# Generated by FakeRAM 2.0
VERSION 5.7 ;
BUSBITCHARS "[]" ;
PROPERTYDEFINITIONS
  MACRO width INTEGER ;
  MACRO depth INTEGER ;
  MACRO banks INTEGER ;
END PROPERTYDEFINITIONS
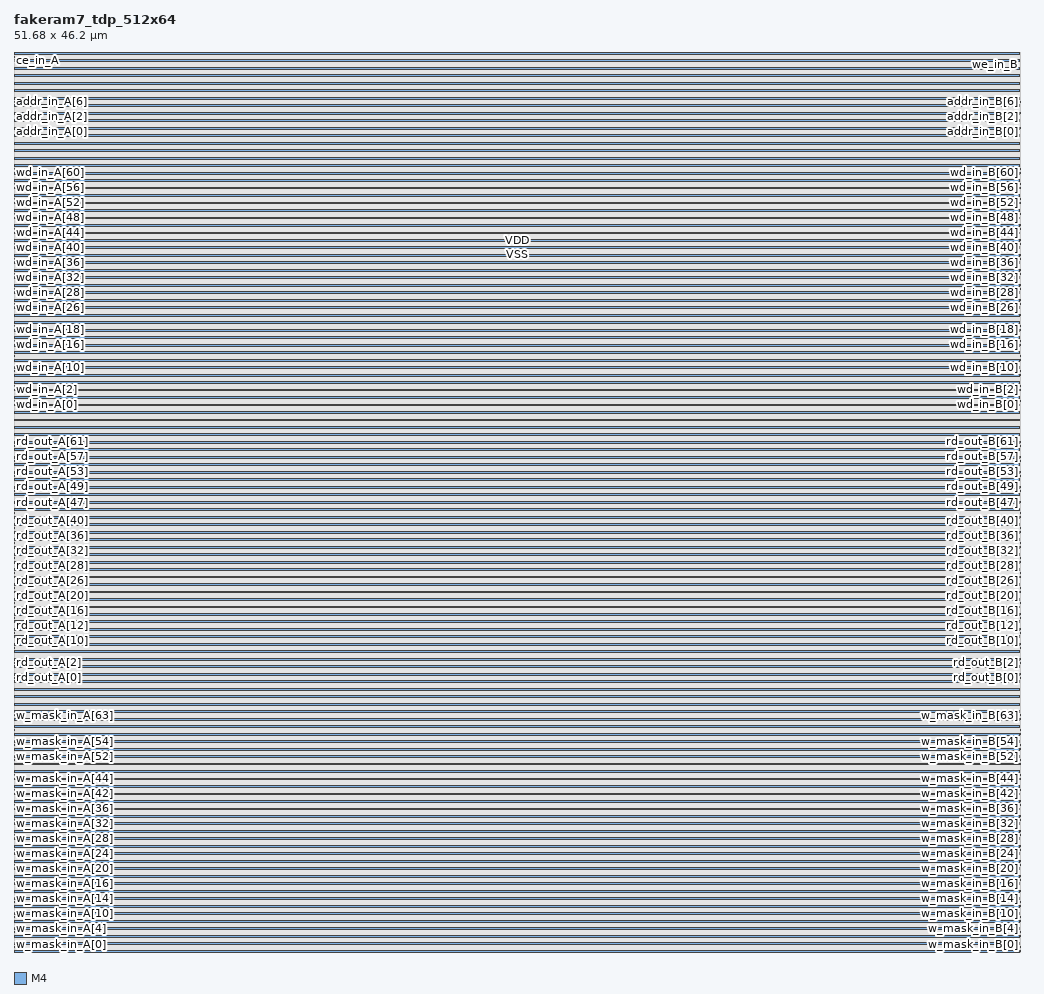
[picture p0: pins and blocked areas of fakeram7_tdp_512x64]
MACRO fakeram7_tdp_512x64
  PROPERTY width 64 ;
  PROPERTY depth 512 ;
  PROPERTY banks 4 ;
  FOREIGN fakeram7_tdp_512x64 0 0 ;
  SYMMETRY X Y ;
  SIZE 51.680 BY 46.200 ;
  CLASS BLOCK ;
  PIN w_mask_in_A[0]
    DIRECTION INPUT ;
    USE SIGNAL ;
    SHAPE ABUTMENT ;
    PORT
      LAYER M4 ;
      RECT 0.000 0.048 0.024 0.072 ;
    END
  END w_mask_in_A[0]
  PIN w_mask_in_B[0]
    DIRECTION INPUT ;
    USE SIGNAL ;
    SHAPE ABUTMENT ;
    PORT
      LAYER M4 ;
      RECT 51.656 0.048 51.680 0.072 ;
    END
  END w_mask_in_B[0]
  PIN w_mask_in_A[1]
    DIRECTION INPUT ;
    USE SIGNAL ;
    SHAPE ABUTMENT ;
    PORT
      LAYER M4 ;
      RECT 0.000 0.240 0.024 0.264 ;
    END
  END w_mask_in_A[1]
  PIN w_mask_in_B[1]
    DIRECTION INPUT ;
    USE SIGNAL ;
    SHAPE ABUTMENT ;
    PORT
      LAYER M4 ;
      RECT 51.656 0.240 51.680 0.264 ;
    END
  END w_mask_in_B[1]
  PIN w_mask_in_A[2]
    DIRECTION INPUT ;
    USE SIGNAL ;
    SHAPE ABUTMENT ;
    PORT
      LAYER M4 ;
      RECT 0.000 0.432 0.024 0.456 ;
    END
  END w_mask_in_A[2]
  PIN w_mask_in_B[2]
    DIRECTION INPUT ;
    USE SIGNAL ;
    SHAPE ABUTMENT ;
    PORT
      LAYER M4 ;
      RECT 51.656 0.432 51.680 0.456 ;
    END
  END w_mask_in_B[2]
  PIN w_mask_in_A[3]
    DIRECTION INPUT ;
    USE SIGNAL ;
    SHAPE ABUTMENT ;
    PORT
      LAYER M4 ;
      RECT 0.000 0.624 0.024 0.648 ;
    END
  END w_mask_in_A[3]
  PIN w_mask_in_B[3]
    DIRECTION INPUT ;
    USE SIGNAL ;
    SHAPE ABUTMENT ;
    PORT
      LAYER M4 ;
      RECT 51.656 0.624 51.680 0.648 ;
    END
  END w_mask_in_B[3]
  PIN w_mask_in_A[4]
    DIRECTION INPUT ;
    USE SIGNAL ;
    SHAPE ABUTMENT ;
    PORT
      LAYER M4 ;
      RECT 0.000 0.816 0.024 0.840 ;
    END
  END w_mask_in_A[4]
  PIN w_mask_in_B[4]
    DIRECTION INPUT ;
    USE SIGNAL ;
    SHAPE ABUTMENT ;
    PORT
      LAYER M4 ;
      RECT 51.656 0.816 51.680 0.840 ;
    END
  END w_mask_in_B[4]
  PIN w_mask_in_A[5]
    DIRECTION INPUT ;
    USE SIGNAL ;
    SHAPE ABUTMENT ;
    PORT
      LAYER M4 ;
      RECT 0.000 1.008 0.024 1.032 ;
    END
  END w_mask_in_A[5]
  PIN w_mask_in_B[5]
    DIRECTION INPUT ;
    USE SIGNAL ;
    SHAPE ABUTMENT ;
    PORT
      LAYER M4 ;
      RECT 51.656 1.008 51.680 1.032 ;
    END
  END w_mask_in_B[5]
  PIN w_mask_in_A[6]
    DIRECTION INPUT ;
    USE SIGNAL ;
    SHAPE ABUTMENT ;
    PORT
      LAYER M4 ;
      RECT 0.000 1.200 0.024 1.224 ;
    END
  END w_mask_in_A[6]
  PIN w_mask_in_B[6]
    DIRECTION INPUT ;
    USE SIGNAL ;
    SHAPE ABUTMENT ;
    PORT
      LAYER M4 ;
      RECT 51.656 1.200 51.680 1.224 ;
    END
  END w_mask_in_B[6]
  PIN w_mask_in_A[7]
    DIRECTION INPUT ;
    USE SIGNAL ;
    SHAPE ABUTMENT ;
    PORT
      LAYER M4 ;
      RECT 0.000 1.392 0.024 1.416 ;
    END
  END w_mask_in_A[7]
  PIN w_mask_in_B[7]
    DIRECTION INPUT ;
    USE SIGNAL ;
    SHAPE ABUTMENT ;
    PORT
      LAYER M4 ;
      RECT 51.656 1.392 51.680 1.416 ;
    END
  END w_mask_in_B[7]
  PIN w_mask_in_A[8]
    DIRECTION INPUT ;
    USE SIGNAL ;
    SHAPE ABUTMENT ;
    PORT
      LAYER M4 ;
      RECT 0.000 1.584 0.024 1.608 ;
    END
  END w_mask_in_A[8]
  PIN w_mask_in_B[8]
    DIRECTION INPUT ;
    USE SIGNAL ;
    SHAPE ABUTMENT ;
    PORT
      LAYER M4 ;
      RECT 51.656 1.584 51.680 1.608 ;
    END
  END w_mask_in_B[8]
  PIN w_mask_in_A[9]
    DIRECTION INPUT ;
    USE SIGNAL ;
    SHAPE ABUTMENT ;
    PORT
      LAYER M4 ;
      RECT 0.000 1.776 0.024 1.800 ;
    END
  END w_mask_in_A[9]
  PIN w_mask_in_B[9]
    DIRECTION INPUT ;
    USE SIGNAL ;
    SHAPE ABUTMENT ;
    PORT
      LAYER M4 ;
      RECT 51.656 1.776 51.680 1.800 ;
    END
  END w_mask_in_B[9]
  PIN w_mask_in_A[10]
    DIRECTION INPUT ;
    USE SIGNAL ;
    SHAPE ABUTMENT ;
    PORT
      LAYER M4 ;
      RECT 0.000 1.968 0.024 1.992 ;
    END
  END w_mask_in_A[10]
  PIN w_mask_in_B[10]
    DIRECTION INPUT ;
    USE SIGNAL ;
    SHAPE ABUTMENT ;
    PORT
      LAYER M4 ;
      RECT 51.656 1.968 51.680 1.992 ;
    END
  END w_mask_in_B[10]
  PIN w_mask_in_A[11]
    DIRECTION INPUT ;
    USE SIGNAL ;
    SHAPE ABUTMENT ;
    PORT
      LAYER M4 ;
      RECT 0.000 2.160 0.024 2.184 ;
    END
  END w_mask_in_A[11]
  PIN w_mask_in_B[11]
    DIRECTION INPUT ;
    USE SIGNAL ;
    SHAPE ABUTMENT ;
    PORT
      LAYER M4 ;
      RECT 51.656 2.160 51.680 2.184 ;
    END
  END w_mask_in_B[11]
  PIN w_mask_in_A[12]
    DIRECTION INPUT ;
    USE SIGNAL ;
    SHAPE ABUTMENT ;
    PORT
      LAYER M4 ;
      RECT 0.000 2.352 0.024 2.376 ;
    END
  END w_mask_in_A[12]
  PIN w_mask_in_B[12]
    DIRECTION INPUT ;
    USE SIGNAL ;
    SHAPE ABUTMENT ;
    PORT
      LAYER M4 ;
      RECT 51.656 2.352 51.680 2.376 ;
    END
  END w_mask_in_B[12]
  PIN w_mask_in_A[13]
    DIRECTION INPUT ;
    USE SIGNAL ;
    SHAPE ABUTMENT ;
    PORT
      LAYER M4 ;
      RECT 0.000 2.544 0.024 2.568 ;
    END
  END w_mask_in_A[13]
  PIN w_mask_in_B[13]
    DIRECTION INPUT ;
    USE SIGNAL ;
    SHAPE ABUTMENT ;
    PORT
      LAYER M4 ;
      RECT 51.656 2.544 51.680 2.568 ;
    END
  END w_mask_in_B[13]
  PIN w_mask_in_A[14]
    DIRECTION INPUT ;
    USE SIGNAL ;
    SHAPE ABUTMENT ;
    PORT
      LAYER M4 ;
      RECT 0.000 2.736 0.024 2.760 ;
    END
  END w_mask_in_A[14]
  PIN w_mask_in_B[14]
    DIRECTION INPUT ;
    USE SIGNAL ;
    SHAPE ABUTMENT ;
    PORT
      LAYER M4 ;
      RECT 51.656 2.736 51.680 2.760 ;
    END
  END w_mask_in_B[14]
  PIN w_mask_in_A[15]
    DIRECTION INPUT ;
    USE SIGNAL ;
    SHAPE ABUTMENT ;
    PORT
      LAYER M4 ;
      RECT 0.000 2.928 0.024 2.952 ;
    END
  END w_mask_in_A[15]
  PIN w_mask_in_B[15]
    DIRECTION INPUT ;
    USE SIGNAL ;
    SHAPE ABUTMENT ;
    PORT
      LAYER M4 ;
      RECT 51.656 2.928 51.680 2.952 ;
    END
  END w_mask_in_B[15]
  PIN w_mask_in_A[16]
    DIRECTION INPUT ;
    USE SIGNAL ;
    SHAPE ABUTMENT ;
    PORT
      LAYER M4 ;
      RECT 0.000 3.120 0.024 3.144 ;
    END
  END w_mask_in_A[16]
  PIN w_mask_in_B[16]
    DIRECTION INPUT ;
    USE SIGNAL ;
    SHAPE ABUTMENT ;
    PORT
      LAYER M4 ;
      RECT 51.656 3.120 51.680 3.144 ;
    END
  END w_mask_in_B[16]
  PIN w_mask_in_A[17]
    DIRECTION INPUT ;
    USE SIGNAL ;
    SHAPE ABUTMENT ;
    PORT
      LAYER M4 ;
      RECT 0.000 3.312 0.024 3.336 ;
    END
  END w_mask_in_A[17]
  PIN w_mask_in_B[17]
    DIRECTION INPUT ;
    USE SIGNAL ;
    SHAPE ABUTMENT ;
    PORT
      LAYER M4 ;
      RECT 51.656 3.312 51.680 3.336 ;
    END
  END w_mask_in_B[17]
  PIN w_mask_in_A[18]
    DIRECTION INPUT ;
    USE SIGNAL ;
    SHAPE ABUTMENT ;
    PORT
      LAYER M4 ;
      RECT 0.000 3.504 0.024 3.528 ;
    END
  END w_mask_in_A[18]
  PIN w_mask_in_B[18]
    DIRECTION INPUT ;
    USE SIGNAL ;
    SHAPE ABUTMENT ;
    PORT
      LAYER M4 ;
      RECT 51.656 3.504 51.680 3.528 ;
    END
  END w_mask_in_B[18]
  PIN w_mask_in_A[19]
    DIRECTION INPUT ;
    USE SIGNAL ;
    SHAPE ABUTMENT ;
    PORT
      LAYER M4 ;
      RECT 0.000 3.696 0.024 3.720 ;
    END
  END w_mask_in_A[19]
  PIN w_mask_in_B[19]
    DIRECTION INPUT ;
    USE SIGNAL ;
    SHAPE ABUTMENT ;
    PORT
      LAYER M4 ;
      RECT 51.656 3.696 51.680 3.720 ;
    END
  END w_mask_in_B[19]
  PIN w_mask_in_A[20]
    DIRECTION INPUT ;
    USE SIGNAL ;
    SHAPE ABUTMENT ;
    PORT
      LAYER M4 ;
      RECT 0.000 3.888 0.024 3.912 ;
    END
  END w_mask_in_A[20]
  PIN w_mask_in_B[20]
    DIRECTION INPUT ;
    USE SIGNAL ;
    SHAPE ABUTMENT ;
    PORT
      LAYER M4 ;
      RECT 51.656 3.888 51.680 3.912 ;
    END
  END w_mask_in_B[20]
  PIN w_mask_in_A[21]
    DIRECTION INPUT ;
    USE SIGNAL ;
    SHAPE ABUTMENT ;
    PORT
      LAYER M4 ;
      RECT 0.000 4.080 0.024 4.104 ;
    END
  END w_mask_in_A[21]
  PIN w_mask_in_B[21]
    DIRECTION INPUT ;
    USE SIGNAL ;
    SHAPE ABUTMENT ;
    PORT
      LAYER M4 ;
      RECT 51.656 4.080 51.680 4.104 ;
    END
  END w_mask_in_B[21]
  PIN w_mask_in_A[22]
    DIRECTION INPUT ;
    USE SIGNAL ;
    SHAPE ABUTMENT ;
    PORT
      LAYER M4 ;
      RECT 0.000 4.272 0.024 4.296 ;
    END
  END w_mask_in_A[22]
  PIN w_mask_in_B[22]
    DIRECTION INPUT ;
    USE SIGNAL ;
    SHAPE ABUTMENT ;
    PORT
      LAYER M4 ;
      RECT 51.656 4.272 51.680 4.296 ;
    END
  END w_mask_in_B[22]
  PIN w_mask_in_A[23]
    DIRECTION INPUT ;
    USE SIGNAL ;
    SHAPE ABUTMENT ;
    PORT
      LAYER M4 ;
      RECT 0.000 4.464 0.024 4.488 ;
    END
  END w_mask_in_A[23]
  PIN w_mask_in_B[23]
    DIRECTION INPUT ;
    USE SIGNAL ;
    SHAPE ABUTMENT ;
    PORT
      LAYER M4 ;
      RECT 51.656 4.464 51.680 4.488 ;
    END
  END w_mask_in_B[23]
  PIN w_mask_in_A[24]
    DIRECTION INPUT ;
    USE SIGNAL ;
    SHAPE ABUTMENT ;
    PORT
      LAYER M4 ;
      RECT 0.000 4.656 0.024 4.680 ;
    END
  END w_mask_in_A[24]
  PIN w_mask_in_B[24]
    DIRECTION INPUT ;
    USE SIGNAL ;
    SHAPE ABUTMENT ;
    PORT
      LAYER M4 ;
      RECT 51.656 4.656 51.680 4.680 ;
    END
  END w_mask_in_B[24]
  PIN w_mask_in_A[25]
    DIRECTION INPUT ;
    USE SIGNAL ;
    SHAPE ABUTMENT ;
    PORT
      LAYER M4 ;
      RECT 0.000 4.848 0.024 4.872 ;
    END
  END w_mask_in_A[25]
  PIN w_mask_in_B[25]
    DIRECTION INPUT ;
    USE SIGNAL ;
    SHAPE ABUTMENT ;
    PORT
      LAYER M4 ;
      RECT 51.656 4.848 51.680 4.872 ;
    END
  END w_mask_in_B[25]
  PIN w_mask_in_A[26]
    DIRECTION INPUT ;
    USE SIGNAL ;
    SHAPE ABUTMENT ;
    PORT
      LAYER M4 ;
      RECT 0.000 5.040 0.024 5.064 ;
    END
  END w_mask_in_A[26]
  PIN w_mask_in_B[26]
    DIRECTION INPUT ;
    USE SIGNAL ;
    SHAPE ABUTMENT ;
    PORT
      LAYER M4 ;
      RECT 51.656 5.040 51.680 5.064 ;
    END
  END w_mask_in_B[26]
  PIN w_mask_in_A[27]
    DIRECTION INPUT ;
    USE SIGNAL ;
    SHAPE ABUTMENT ;
    PORT
      LAYER M4 ;
      RECT 0.000 5.232 0.024 5.256 ;
    END
  END w_mask_in_A[27]
  PIN w_mask_in_B[27]
    DIRECTION INPUT ;
    USE SIGNAL ;
    SHAPE ABUTMENT ;
    PORT
      LAYER M4 ;
      RECT 51.656 5.232 51.680 5.256 ;
    END
  END w_mask_in_B[27]
  PIN w_mask_in_A[28]
    DIRECTION INPUT ;
    USE SIGNAL ;
    SHAPE ABUTMENT ;
    PORT
      LAYER M4 ;
      RECT 0.000 5.424 0.024 5.448 ;
    END
  END w_mask_in_A[28]
  PIN w_mask_in_B[28]
    DIRECTION INPUT ;
    USE SIGNAL ;
    SHAPE ABUTMENT ;
    PORT
      LAYER M4 ;
      RECT 51.656 5.424 51.680 5.448 ;
    END
  END w_mask_in_B[28]
  PIN w_mask_in_A[29]
    DIRECTION INPUT ;
    USE SIGNAL ;
    SHAPE ABUTMENT ;
    PORT
      LAYER M4 ;
      RECT 0.000 5.616 0.024 5.640 ;
    END
  END w_mask_in_A[29]
  PIN w_mask_in_B[29]
    DIRECTION INPUT ;
    USE SIGNAL ;
    SHAPE ABUTMENT ;
    PORT
      LAYER M4 ;
      RECT 51.656 5.616 51.680 5.640 ;
    END
  END w_mask_in_B[29]
  PIN w_mask_in_A[30]
    DIRECTION INPUT ;
    USE SIGNAL ;
    SHAPE ABUTMENT ;
    PORT
      LAYER M4 ;
      RECT 0.000 5.808 0.024 5.832 ;
    END
  END w_mask_in_A[30]
  PIN w_mask_in_B[30]
    DIRECTION INPUT ;
    USE SIGNAL ;
    SHAPE ABUTMENT ;
    PORT
      LAYER M4 ;
      RECT 51.656 5.808 51.680 5.832 ;
    END
  END w_mask_in_B[30]
  PIN w_mask_in_A[31]
    DIRECTION INPUT ;
    USE SIGNAL ;
    SHAPE ABUTMENT ;
    PORT
      LAYER M4 ;
      RECT 0.000 6.000 0.024 6.024 ;
    END
  END w_mask_in_A[31]
  PIN w_mask_in_B[31]
    DIRECTION INPUT ;
    USE SIGNAL ;
    SHAPE ABUTMENT ;
    PORT
      LAYER M4 ;
      RECT 51.656 6.000 51.680 6.024 ;
    END
  END w_mask_in_B[31]
  PIN w_mask_in_A[32]
    DIRECTION INPUT ;
    USE SIGNAL ;
    SHAPE ABUTMENT ;
    PORT
      LAYER M4 ;
      RECT 0.000 6.192 0.024 6.216 ;
    END
  END w_mask_in_A[32]
  PIN w_mask_in_B[32]
    DIRECTION INPUT ;
    USE SIGNAL ;
    SHAPE ABUTMENT ;
    PORT
      LAYER M4 ;
      RECT 51.656 6.192 51.680 6.216 ;
    END
  END w_mask_in_B[32]
  PIN w_mask_in_A[33]
    DIRECTION INPUT ;
    USE SIGNAL ;
    SHAPE ABUTMENT ;
    PORT
      LAYER M4 ;
      RECT 0.000 6.384 0.024 6.408 ;
    END
  END w_mask_in_A[33]
  PIN w_mask_in_B[33]
    DIRECTION INPUT ;
    USE SIGNAL ;
    SHAPE ABUTMENT ;
    PORT
      LAYER M4 ;
      RECT 51.656 6.384 51.680 6.408 ;
    END
  END w_mask_in_B[33]
  PIN w_mask_in_A[34]
    DIRECTION INPUT ;
    USE SIGNAL ;
    SHAPE ABUTMENT ;
    PORT
      LAYER M4 ;
      RECT 0.000 6.576 0.024 6.600 ;
    END
  END w_mask_in_A[34]
  PIN w_mask_in_B[34]
    DIRECTION INPUT ;
    USE SIGNAL ;
    SHAPE ABUTMENT ;
    PORT
      LAYER M4 ;
      RECT 51.656 6.576 51.680 6.600 ;
    END
  END w_mask_in_B[34]
  PIN w_mask_in_A[35]
    DIRECTION INPUT ;
    USE SIGNAL ;
    SHAPE ABUTMENT ;
    PORT
      LAYER M4 ;
      RECT 0.000 6.768 0.024 6.792 ;
    END
  END w_mask_in_A[35]
  PIN w_mask_in_B[35]
    DIRECTION INPUT ;
    USE SIGNAL ;
    SHAPE ABUTMENT ;
    PORT
      LAYER M4 ;
      RECT 51.656 6.768 51.680 6.792 ;
    END
  END w_mask_in_B[35]
  PIN w_mask_in_A[36]
    DIRECTION INPUT ;
    USE SIGNAL ;
    SHAPE ABUTMENT ;
    PORT
      LAYER M4 ;
      RECT 0.000 6.960 0.024 6.984 ;
    END
  END w_mask_in_A[36]
  PIN w_mask_in_B[36]
    DIRECTION INPUT ;
    USE SIGNAL ;
    SHAPE ABUTMENT ;
    PORT
      LAYER M4 ;
      RECT 51.656 6.960 51.680 6.984 ;
    END
  END w_mask_in_B[36]
  PIN w_mask_in_A[37]
    DIRECTION INPUT ;
    USE SIGNAL ;
    SHAPE ABUTMENT ;
    PORT
      LAYER M4 ;
      RECT 0.000 7.152 0.024 7.176 ;
    END
  END w_mask_in_A[37]
  PIN w_mask_in_B[37]
    DIRECTION INPUT ;
    USE SIGNAL ;
    SHAPE ABUTMENT ;
    PORT
      LAYER M4 ;
      RECT 51.656 7.152 51.680 7.176 ;
    END
  END w_mask_in_B[37]
  PIN w_mask_in_A[38]
    DIRECTION INPUT ;
    USE SIGNAL ;
    SHAPE ABUTMENT ;
    PORT
      LAYER M4 ;
      RECT 0.000 7.344 0.024 7.368 ;
    END
  END w_mask_in_A[38]
  PIN w_mask_in_B[38]
    DIRECTION INPUT ;
    USE SIGNAL ;
    SHAPE ABUTMENT ;
    PORT
      LAYER M4 ;
      RECT 51.656 7.344 51.680 7.368 ;
    END
  END w_mask_in_B[38]
  PIN w_mask_in_A[39]
    DIRECTION INPUT ;
    USE SIGNAL ;
    SHAPE ABUTMENT ;
    PORT
      LAYER M4 ;
      RECT 0.000 7.536 0.024 7.560 ;
    END
  END w_mask_in_A[39]
  PIN w_mask_in_B[39]
    DIRECTION INPUT ;
    USE SIGNAL ;
    SHAPE ABUTMENT ;
    PORT
      LAYER M4 ;
      RECT 51.656 7.536 51.680 7.560 ;
    END
  END w_mask_in_B[39]
  PIN w_mask_in_A[40]
    DIRECTION INPUT ;
    USE SIGNAL ;
    SHAPE ABUTMENT ;
    PORT
      LAYER M4 ;
      RECT 0.000 7.728 0.024 7.752 ;
    END
  END w_mask_in_A[40]
  PIN w_mask_in_B[40]
    DIRECTION INPUT ;
    USE SIGNAL ;
    SHAPE ABUTMENT ;
    PORT
      LAYER M4 ;
      RECT 51.656 7.728 51.680 7.752 ;
    END
  END w_mask_in_B[40]
  PIN w_mask_in_A[41]
    DIRECTION INPUT ;
    USE SIGNAL ;
    SHAPE ABUTMENT ;
    PORT
      LAYER M4 ;
      RECT 0.000 7.920 0.024 7.944 ;
    END
  END w_mask_in_A[41]
  PIN w_mask_in_B[41]
    DIRECTION INPUT ;
    USE SIGNAL ;
    SHAPE ABUTMENT ;
    PORT
      LAYER M4 ;
      RECT 51.656 7.920 51.680 7.944 ;
    END
  END w_mask_in_B[41]
  PIN w_mask_in_A[42]
    DIRECTION INPUT ;
    USE SIGNAL ;
    SHAPE ABUTMENT ;
    PORT
      LAYER M4 ;
      RECT 0.000 8.112 0.024 8.136 ;
    END
  END w_mask_in_A[42]
  PIN w_mask_in_B[42]
    DIRECTION INPUT ;
    USE SIGNAL ;
    SHAPE ABUTMENT ;
    PORT
      LAYER M4 ;
      RECT 51.656 8.112 51.680 8.136 ;
    END
  END w_mask_in_B[42]
  PIN w_mask_in_A[43]
    DIRECTION INPUT ;
    USE SIGNAL ;
    SHAPE ABUTMENT ;
    PORT
      LAYER M4 ;
      RECT 0.000 8.304 0.024 8.328 ;
    END
  END w_mask_in_A[43]
  PIN w_mask_in_B[43]
    DIRECTION INPUT ;
    USE SIGNAL ;
    SHAPE ABUTMENT ;
    PORT
      LAYER M4 ;
      RECT 51.656 8.304 51.680 8.328 ;
    END
  END w_mask_in_B[43]
  PIN w_mask_in_A[44]
    DIRECTION INPUT ;
    USE SIGNAL ;
    SHAPE ABUTMENT ;
    PORT
      LAYER M4 ;
      RECT 0.000 8.496 0.024 8.520 ;
    END
  END w_mask_in_A[44]
  PIN w_mask_in_B[44]
    DIRECTION INPUT ;
    USE SIGNAL ;
    SHAPE ABUTMENT ;
    PORT
      LAYER M4 ;
      RECT 51.656 8.496 51.680 8.520 ;
    END
  END w_mask_in_B[44]
  PIN w_mask_in_A[45]
    DIRECTION INPUT ;
    USE SIGNAL ;
    SHAPE ABUTMENT ;
    PORT
      LAYER M4 ;
      RECT 0.000 8.688 0.024 8.712 ;
    END
  END w_mask_in_A[45]
  PIN w_mask_in_B[45]
    DIRECTION INPUT ;
    USE SIGNAL ;
    SHAPE ABUTMENT ;
    PORT
      LAYER M4 ;
      RECT 51.656 8.688 51.680 8.712 ;
    END
  END w_mask_in_B[45]
  PIN w_mask_in_A[46]
    DIRECTION INPUT ;
    USE SIGNAL ;
    SHAPE ABUTMENT ;
    PORT
      LAYER M4 ;
      RECT 0.000 8.880 0.024 8.904 ;
    END
  END w_mask_in_A[46]
  PIN w_mask_in_B[46]
    DIRECTION INPUT ;
    USE SIGNAL ;
    SHAPE ABUTMENT ;
    PORT
      LAYER M4 ;
      RECT 51.656 8.880 51.680 8.904 ;
    END
  END w_mask_in_B[46]
  PIN w_mask_in_A[47]
    DIRECTION INPUT ;
    USE SIGNAL ;
    SHAPE ABUTMENT ;
    PORT
      LAYER M4 ;
      RECT 0.000 9.072 0.024 9.096 ;
    END
  END w_mask_in_A[47]
  PIN w_mask_in_B[47]
    DIRECTION INPUT ;
    USE SIGNAL ;
    SHAPE ABUTMENT ;
    PORT
      LAYER M4 ;
      RECT 51.656 9.072 51.680 9.096 ;
    END
  END w_mask_in_B[47]
  PIN w_mask_in_A[48]
    DIRECTION INPUT ;
    USE SIGNAL ;
    SHAPE ABUTMENT ;
    PORT
      LAYER M4 ;
      RECT 0.000 9.264 0.024 9.288 ;
    END
  END w_mask_in_A[48]
  PIN w_mask_in_B[48]
    DIRECTION INPUT ;
    USE SIGNAL ;
    SHAPE ABUTMENT ;
    PORT
      LAYER M4 ;
      RECT 51.656 9.264 51.680 9.288 ;
    END
  END w_mask_in_B[48]
  PIN w_mask_in_A[49]
    DIRECTION INPUT ;
    USE SIGNAL ;
    SHAPE ABUTMENT ;
    PORT
      LAYER M4 ;
      RECT 0.000 9.456 0.024 9.480 ;
    END
  END w_mask_in_A[49]
  PIN w_mask_in_B[49]
    DIRECTION INPUT ;
    USE SIGNAL ;
    SHAPE ABUTMENT ;
    PORT
      LAYER M4 ;
      RECT 51.656 9.456 51.680 9.480 ;
    END
  END w_mask_in_B[49]
  PIN w_mask_in_A[50]
    DIRECTION INPUT ;
    USE SIGNAL ;
    SHAPE ABUTMENT ;
    PORT
      LAYER M4 ;
      RECT 0.000 9.648 0.024 9.672 ;
    END
  END w_mask_in_A[50]
  PIN w_mask_in_B[50]
    DIRECTION INPUT ;
    USE SIGNAL ;
    SHAPE ABUTMENT ;
    PORT
      LAYER M4 ;
      RECT 51.656 9.648 51.680 9.672 ;
    END
  END w_mask_in_B[50]
  PIN w_mask_in_A[51]
    DIRECTION INPUT ;
    USE SIGNAL ;
    SHAPE ABUTMENT ;
    PORT
      LAYER M4 ;
      RECT 0.000 9.840 0.024 9.864 ;
    END
  END w_mask_in_A[51]
  PIN w_mask_in_B[51]
    DIRECTION INPUT ;
    USE SIGNAL ;
    SHAPE ABUTMENT ;
    PORT
      LAYER M4 ;
      RECT 51.656 9.840 51.680 9.864 ;
    END
  END w_mask_in_B[51]
  PIN w_mask_in_A[52]
    DIRECTION INPUT ;
    USE SIGNAL ;
    SHAPE ABUTMENT ;
    PORT
      LAYER M4 ;
      RECT 0.000 10.032 0.024 10.056 ;
    END
  END w_mask_in_A[52]
  PIN w_mask_in_B[52]
    DIRECTION INPUT ;
    USE SIGNAL ;
    SHAPE ABUTMENT ;
    PORT
      LAYER M4 ;
      RECT 51.656 10.032 51.680 10.056 ;
    END
  END w_mask_in_B[52]
  PIN w_mask_in_A[53]
    DIRECTION INPUT ;
    USE SIGNAL ;
    SHAPE ABUTMENT ;
    PORT
      LAYER M4 ;
      RECT 0.000 10.224 0.024 10.248 ;
    END
  END w_mask_in_A[53]
  PIN w_mask_in_B[53]
    DIRECTION INPUT ;
    USE SIGNAL ;
    SHAPE ABUTMENT ;
    PORT
      LAYER M4 ;
      RECT 51.656 10.224 51.680 10.248 ;
    END
  END w_mask_in_B[53]
  PIN w_mask_in_A[54]
    DIRECTION INPUT ;
    USE SIGNAL ;
    SHAPE ABUTMENT ;
    PORT
      LAYER M4 ;
      RECT 0.000 10.416 0.024 10.440 ;
    END
  END w_mask_in_A[54]
  PIN w_mask_in_B[54]
    DIRECTION INPUT ;
    USE SIGNAL ;
    SHAPE ABUTMENT ;
    PORT
      LAYER M4 ;
      RECT 51.656 10.416 51.680 10.440 ;
    END
  END w_mask_in_B[54]
  PIN w_mask_in_A[55]
    DIRECTION INPUT ;
    USE SIGNAL ;
    SHAPE ABUTMENT ;
    PORT
      LAYER M4 ;
      RECT 0.000 10.608 0.024 10.632 ;
    END
  END w_mask_in_A[55]
  PIN w_mask_in_B[55]
    DIRECTION INPUT ;
    USE SIGNAL ;
    SHAPE ABUTMENT ;
    PORT
      LAYER M4 ;
      RECT 51.656 10.608 51.680 10.632 ;
    END
  END w_mask_in_B[55]
  PIN w_mask_in_A[56]
    DIRECTION INPUT ;
    USE SIGNAL ;
    SHAPE ABUTMENT ;
    PORT
      LAYER M4 ;
      RECT 0.000 10.800 0.024 10.824 ;
    END
  END w_mask_in_A[56]
  PIN w_mask_in_B[56]
    DIRECTION INPUT ;
    USE SIGNAL ;
    SHAPE ABUTMENT ;
    PORT
      LAYER M4 ;
      RECT 51.656 10.800 51.680 10.824 ;
    END
  END w_mask_in_B[56]
  PIN w_mask_in_A[57]
    DIRECTION INPUT ;
    USE SIGNAL ;
    SHAPE ABUTMENT ;
    PORT
      LAYER M4 ;
      RECT 0.000 10.992 0.024 11.016 ;
    END
  END w_mask_in_A[57]
  PIN w_mask_in_B[57]
    DIRECTION INPUT ;
    USE SIGNAL ;
    SHAPE ABUTMENT ;
    PORT
      LAYER M4 ;
      RECT 51.656 10.992 51.680 11.016 ;
    END
  END w_mask_in_B[57]
  PIN w_mask_in_A[58]
    DIRECTION INPUT ;
    USE SIGNAL ;
    SHAPE ABUTMENT ;
    PORT
      LAYER M4 ;
      RECT 0.000 11.184 0.024 11.208 ;
    END
  END w_mask_in_A[58]
  PIN w_mask_in_B[58]
    DIRECTION INPUT ;
    USE SIGNAL ;
    SHAPE ABUTMENT ;
    PORT
      LAYER M4 ;
      RECT 51.656 11.184 51.680 11.208 ;
    END
  END w_mask_in_B[58]
  PIN w_mask_in_A[59]
    DIRECTION INPUT ;
    USE SIGNAL ;
    SHAPE ABUTMENT ;
    PORT
      LAYER M4 ;
      RECT 0.000 11.376 0.024 11.400 ;
    END
  END w_mask_in_A[59]
  PIN w_mask_in_B[59]
    DIRECTION INPUT ;
    USE SIGNAL ;
    SHAPE ABUTMENT ;
    PORT
      LAYER M4 ;
      RECT 51.656 11.376 51.680 11.400 ;
    END
  END w_mask_in_B[59]
  PIN w_mask_in_A[60]
    DIRECTION INPUT ;
    USE SIGNAL ;
    SHAPE ABUTMENT ;
    PORT
      LAYER M4 ;
      RECT 0.000 11.568 0.024 11.592 ;
    END
  END w_mask_in_A[60]
  PIN w_mask_in_B[60]
    DIRECTION INPUT ;
    USE SIGNAL ;
    SHAPE ABUTMENT ;
    PORT
      LAYER M4 ;
      RECT 51.656 11.568 51.680 11.592 ;
    END
  END w_mask_in_B[60]
  PIN w_mask_in_A[61]
    DIRECTION INPUT ;
    USE SIGNAL ;
    SHAPE ABUTMENT ;
    PORT
      LAYER M4 ;
      RECT 0.000 11.760 0.024 11.784 ;
    END
  END w_mask_in_A[61]
  PIN w_mask_in_B[61]
    DIRECTION INPUT ;
    USE SIGNAL ;
    SHAPE ABUTMENT ;
    PORT
      LAYER M4 ;
      RECT 51.656 11.760 51.680 11.784 ;
    END
  END w_mask_in_B[61]
  PIN w_mask_in_A[62]
    DIRECTION INPUT ;
    USE SIGNAL ;
    SHAPE ABUTMENT ;
    PORT
      LAYER M4 ;
      RECT 0.000 11.952 0.024 11.976 ;
    END
  END w_mask_in_A[62]
  PIN w_mask_in_B[62]
    DIRECTION INPUT ;
    USE SIGNAL ;
    SHAPE ABUTMENT ;
    PORT
      LAYER M4 ;
      RECT 51.656 11.952 51.680 11.976 ;
    END
  END w_mask_in_B[62]
  PIN w_mask_in_A[63]
    DIRECTION INPUT ;
    USE SIGNAL ;
    SHAPE ABUTMENT ;
    PORT
      LAYER M4 ;
      RECT 0.000 12.144 0.024 12.168 ;
    END
  END w_mask_in_A[63]
  PIN w_mask_in_B[63]
    DIRECTION INPUT ;
    USE SIGNAL ;
    SHAPE ABUTMENT ;
    PORT
      LAYER M4 ;
      RECT 51.656 12.144 51.680 12.168 ;
    END
  END w_mask_in_B[63]
  PIN rd_out_A[0]
    DIRECTION OUTPUT ;
    USE SIGNAL ;
    SHAPE ABUTMENT ;
    PORT
      LAYER M4 ;
      RECT 0.000 14.064 0.024 14.088 ;
    END
  END rd_out_A[0]
  PIN rd_out_B[0]
    DIRECTION OUTPUT ;
    USE SIGNAL ;
    SHAPE ABUTMENT ;
    PORT
      LAYER M4 ;
      RECT 51.656 14.064 51.680 14.088 ;
    END
  END rd_out_B[0]
  PIN rd_out_A[1]
    DIRECTION OUTPUT ;
    USE SIGNAL ;
    SHAPE ABUTMENT ;
    PORT
      LAYER M4 ;
      RECT 0.000 14.256 0.024 14.280 ;
    END
  END rd_out_A[1]
  PIN rd_out_B[1]
    DIRECTION OUTPUT ;
    USE SIGNAL ;
    SHAPE ABUTMENT ;
    PORT
      LAYER M4 ;
      RECT 51.656 14.256 51.680 14.280 ;
    END
  END rd_out_B[1]
  PIN rd_out_A[2]
    DIRECTION OUTPUT ;
    USE SIGNAL ;
    SHAPE ABUTMENT ;
    PORT
      LAYER M4 ;
      RECT 0.000 14.448 0.024 14.472 ;
    END
  END rd_out_A[2]
  PIN rd_out_B[2]
    DIRECTION OUTPUT ;
    USE SIGNAL ;
    SHAPE ABUTMENT ;
    PORT
      LAYER M4 ;
      RECT 51.656 14.448 51.680 14.472 ;
    END
  END rd_out_B[2]
  PIN rd_out_A[3]
    DIRECTION OUTPUT ;
    USE SIGNAL ;
    SHAPE ABUTMENT ;
    PORT
      LAYER M4 ;
      RECT 0.000 14.640 0.024 14.664 ;
    END
  END rd_out_A[3]
  PIN rd_out_B[3]
    DIRECTION OUTPUT ;
    USE SIGNAL ;
    SHAPE ABUTMENT ;
    PORT
      LAYER M4 ;
      RECT 51.656 14.640 51.680 14.664 ;
    END
  END rd_out_B[3]
  PIN rd_out_A[4]
    DIRECTION OUTPUT ;
    USE SIGNAL ;
    SHAPE ABUTMENT ;
    PORT
      LAYER M4 ;
      RECT 0.000 14.832 0.024 14.856 ;
    END
  END rd_out_A[4]
  PIN rd_out_B[4]
    DIRECTION OUTPUT ;
    USE SIGNAL ;
    SHAPE ABUTMENT ;
    PORT
      LAYER M4 ;
      RECT 51.656 14.832 51.680 14.856 ;
    END
  END rd_out_B[4]
  PIN rd_out_A[5]
    DIRECTION OUTPUT ;
    USE SIGNAL ;
    SHAPE ABUTMENT ;
    PORT
      LAYER M4 ;
      RECT 0.000 15.024 0.024 15.048 ;
    END
  END rd_out_A[5]
  PIN rd_out_B[5]
    DIRECTION OUTPUT ;
    USE SIGNAL ;
    SHAPE ABUTMENT ;
    PORT
      LAYER M4 ;
      RECT 51.656 15.024 51.680 15.048 ;
    END
  END rd_out_B[5]
  PIN rd_out_A[6]
    DIRECTION OUTPUT ;
    USE SIGNAL ;
    SHAPE ABUTMENT ;
    PORT
      LAYER M4 ;
      RECT 0.000 15.216 0.024 15.240 ;
    END
  END rd_out_A[6]
  PIN rd_out_B[6]
    DIRECTION OUTPUT ;
    USE SIGNAL ;
    SHAPE ABUTMENT ;
    PORT
      LAYER M4 ;
      RECT 51.656 15.216 51.680 15.240 ;
    END
  END rd_out_B[6]
  PIN rd_out_A[7]
    DIRECTION OUTPUT ;
    USE SIGNAL ;
    SHAPE ABUTMENT ;
    PORT
      LAYER M4 ;
      RECT 0.000 15.408 0.024 15.432 ;
    END
  END rd_out_A[7]
  PIN rd_out_B[7]
    DIRECTION OUTPUT ;
    USE SIGNAL ;
    SHAPE ABUTMENT ;
    PORT
      LAYER M4 ;
      RECT 51.656 15.408 51.680 15.432 ;
    END
  END rd_out_B[7]
  PIN rd_out_A[8]
    DIRECTION OUTPUT ;
    USE SIGNAL ;
    SHAPE ABUTMENT ;
    PORT
      LAYER M4 ;
      RECT 0.000 15.600 0.024 15.624 ;
    END
  END rd_out_A[8]
  PIN rd_out_B[8]
    DIRECTION OUTPUT ;
    USE SIGNAL ;
    SHAPE ABUTMENT ;
    PORT
      LAYER M4 ;
      RECT 51.656 15.600 51.680 15.624 ;
    END
  END rd_out_B[8]
  PIN rd_out_A[9]
    DIRECTION OUTPUT ;
    USE SIGNAL ;
    SHAPE ABUTMENT ;
    PORT
      LAYER M4 ;
      RECT 0.000 15.792 0.024 15.816 ;
    END
  END rd_out_A[9]
  PIN rd_out_B[9]
    DIRECTION OUTPUT ;
    USE SIGNAL ;
    SHAPE ABUTMENT ;
    PORT
      LAYER M4 ;
      RECT 51.656 15.792 51.680 15.816 ;
    END
  END rd_out_B[9]
  PIN rd_out_A[10]
    DIRECTION OUTPUT ;
    USE SIGNAL ;
    SHAPE ABUTMENT ;
    PORT
      LAYER M4 ;
      RECT 0.000 15.984 0.024 16.008 ;
    END
  END rd_out_A[10]
  PIN rd_out_B[10]
    DIRECTION OUTPUT ;
    USE SIGNAL ;
    SHAPE ABUTMENT ;
    PORT
      LAYER M4 ;
      RECT 51.656 15.984 51.680 16.008 ;
    END
  END rd_out_B[10]
  PIN rd_out_A[11]
    DIRECTION OUTPUT ;
    USE SIGNAL ;
    SHAPE ABUTMENT ;
    PORT
      LAYER M4 ;
      RECT 0.000 16.176 0.024 16.200 ;
    END
  END rd_out_A[11]
  PIN rd_out_B[11]
    DIRECTION OUTPUT ;
    USE SIGNAL ;
    SHAPE ABUTMENT ;
    PORT
      LAYER M4 ;
      RECT 51.656 16.176 51.680 16.200 ;
    END
  END rd_out_B[11]
  PIN rd_out_A[12]
    DIRECTION OUTPUT ;
    USE SIGNAL ;
    SHAPE ABUTMENT ;
    PORT
      LAYER M4 ;
      RECT 0.000 16.368 0.024 16.392 ;
    END
  END rd_out_A[12]
  PIN rd_out_B[12]
    DIRECTION OUTPUT ;
    USE SIGNAL ;
    SHAPE ABUTMENT ;
    PORT
      LAYER M4 ;
      RECT 51.656 16.368 51.680 16.392 ;
    END
  END rd_out_B[12]
  PIN rd_out_A[13]
    DIRECTION OUTPUT ;
    USE SIGNAL ;
    SHAPE ABUTMENT ;
    PORT
      LAYER M4 ;
      RECT 0.000 16.560 0.024 16.584 ;
    END
  END rd_out_A[13]
  PIN rd_out_B[13]
    DIRECTION OUTPUT ;
    USE SIGNAL ;
    SHAPE ABUTMENT ;
    PORT
      LAYER M4 ;
      RECT 51.656 16.560 51.680 16.584 ;
    END
  END rd_out_B[13]
  PIN rd_out_A[14]
    DIRECTION OUTPUT ;
    USE SIGNAL ;
    SHAPE ABUTMENT ;
    PORT
      LAYER M4 ;
      RECT 0.000 16.752 0.024 16.776 ;
    END
  END rd_out_A[14]
  PIN rd_out_B[14]
    DIRECTION OUTPUT ;
    USE SIGNAL ;
    SHAPE ABUTMENT ;
    PORT
      LAYER M4 ;
      RECT 51.656 16.752 51.680 16.776 ;
    END
  END rd_out_B[14]
  PIN rd_out_A[15]
    DIRECTION OUTPUT ;
    USE SIGNAL ;
    SHAPE ABUTMENT ;
    PORT
      LAYER M4 ;
      RECT 0.000 16.944 0.024 16.968 ;
    END
  END rd_out_A[15]
  PIN rd_out_B[15]
    DIRECTION OUTPUT ;
    USE SIGNAL ;
    SHAPE ABUTMENT ;
    PORT
      LAYER M4 ;
      RECT 51.656 16.944 51.680 16.968 ;
    END
  END rd_out_B[15]
  PIN rd_out_A[16]
    DIRECTION OUTPUT ;
    USE SIGNAL ;
    SHAPE ABUTMENT ;
    PORT
      LAYER M4 ;
      RECT 0.000 17.136 0.024 17.160 ;
    END
  END rd_out_A[16]
  PIN rd_out_B[16]
    DIRECTION OUTPUT ;
    USE SIGNAL ;
    SHAPE ABUTMENT ;
    PORT
      LAYER M4 ;
      RECT 51.656 17.136 51.680 17.160 ;
    END
  END rd_out_B[16]
  PIN rd_out_A[17]
    DIRECTION OUTPUT ;
    USE SIGNAL ;
    SHAPE ABUTMENT ;
    PORT
      LAYER M4 ;
      RECT 0.000 17.328 0.024 17.352 ;
    END
  END rd_out_A[17]
  PIN rd_out_B[17]
    DIRECTION OUTPUT ;
    USE SIGNAL ;
    SHAPE ABUTMENT ;
    PORT
      LAYER M4 ;
      RECT 51.656 17.328 51.680 17.352 ;
    END
  END rd_out_B[17]
  PIN rd_out_A[18]
    DIRECTION OUTPUT ;
    USE SIGNAL ;
    SHAPE ABUTMENT ;
    PORT
      LAYER M4 ;
      RECT 0.000 17.520 0.024 17.544 ;
    END
  END rd_out_A[18]
  PIN rd_out_B[18]
    DIRECTION OUTPUT ;
    USE SIGNAL ;
    SHAPE ABUTMENT ;
    PORT
      LAYER M4 ;
      RECT 51.656 17.520 51.680 17.544 ;
    END
  END rd_out_B[18]
  PIN rd_out_A[19]
    DIRECTION OUTPUT ;
    USE SIGNAL ;
    SHAPE ABUTMENT ;
    PORT
      LAYER M4 ;
      RECT 0.000 17.712 0.024 17.736 ;
    END
  END rd_out_A[19]
  PIN rd_out_B[19]
    DIRECTION OUTPUT ;
    USE SIGNAL ;
    SHAPE ABUTMENT ;
    PORT
      LAYER M4 ;
      RECT 51.656 17.712 51.680 17.736 ;
    END
  END rd_out_B[19]
  PIN rd_out_A[20]
    DIRECTION OUTPUT ;
    USE SIGNAL ;
    SHAPE ABUTMENT ;
    PORT
      LAYER M4 ;
      RECT 0.000 17.904 0.024 17.928 ;
    END
  END rd_out_A[20]
  PIN rd_out_B[20]
    DIRECTION OUTPUT ;
    USE SIGNAL ;
    SHAPE ABUTMENT ;
    PORT
      LAYER M4 ;
      RECT 51.656 17.904 51.680 17.928 ;
    END
  END rd_out_B[20]
  PIN rd_out_A[21]
    DIRECTION OUTPUT ;
    USE SIGNAL ;
    SHAPE ABUTMENT ;
    PORT
      LAYER M4 ;
      RECT 0.000 18.096 0.024 18.120 ;
    END
  END rd_out_A[21]
  PIN rd_out_B[21]
    DIRECTION OUTPUT ;
    USE SIGNAL ;
    SHAPE ABUTMENT ;
    PORT
      LAYER M4 ;
      RECT 51.656 18.096 51.680 18.120 ;
    END
  END rd_out_B[21]
  PIN rd_out_A[22]
    DIRECTION OUTPUT ;
    USE SIGNAL ;
    SHAPE ABUTMENT ;
    PORT
      LAYER M4 ;
      RECT 0.000 18.288 0.024 18.312 ;
    END
  END rd_out_A[22]
  PIN rd_out_B[22]
    DIRECTION OUTPUT ;
    USE SIGNAL ;
    SHAPE ABUTMENT ;
    PORT
      LAYER M4 ;
      RECT 51.656 18.288 51.680 18.312 ;
    END
  END rd_out_B[22]
  PIN rd_out_A[23]
    DIRECTION OUTPUT ;
    USE SIGNAL ;
    SHAPE ABUTMENT ;
    PORT
      LAYER M4 ;
      RECT 0.000 18.480 0.024 18.504 ;
    END
  END rd_out_A[23]
  PIN rd_out_B[23]
    DIRECTION OUTPUT ;
    USE SIGNAL ;
    SHAPE ABUTMENT ;
    PORT
      LAYER M4 ;
      RECT 51.656 18.480 51.680 18.504 ;
    END
  END rd_out_B[23]
  PIN rd_out_A[24]
    DIRECTION OUTPUT ;
    USE SIGNAL ;
    SHAPE ABUTMENT ;
    PORT
      LAYER M4 ;
      RECT 0.000 18.672 0.024 18.696 ;
    END
  END rd_out_A[24]
  PIN rd_out_B[24]
    DIRECTION OUTPUT ;
    USE SIGNAL ;
    SHAPE ABUTMENT ;
    PORT
      LAYER M4 ;
      RECT 51.656 18.672 51.680 18.696 ;
    END
  END rd_out_B[24]
  PIN rd_out_A[25]
    DIRECTION OUTPUT ;
    USE SIGNAL ;
    SHAPE ABUTMENT ;
    PORT
      LAYER M4 ;
      RECT 0.000 18.864 0.024 18.888 ;
    END
  END rd_out_A[25]
  PIN rd_out_B[25]
    DIRECTION OUTPUT ;
    USE SIGNAL ;
    SHAPE ABUTMENT ;
    PORT
      LAYER M4 ;
      RECT 51.656 18.864 51.680 18.888 ;
    END
  END rd_out_B[25]
  PIN rd_out_A[26]
    DIRECTION OUTPUT ;
    USE SIGNAL ;
    SHAPE ABUTMENT ;
    PORT
      LAYER M4 ;
      RECT 0.000 19.056 0.024 19.080 ;
    END
  END rd_out_A[26]
  PIN rd_out_B[26]
    DIRECTION OUTPUT ;
    USE SIGNAL ;
    SHAPE ABUTMENT ;
    PORT
      LAYER M4 ;
      RECT 51.656 19.056 51.680 19.080 ;
    END
  END rd_out_B[26]
  PIN rd_out_A[27]
    DIRECTION OUTPUT ;
    USE SIGNAL ;
    SHAPE ABUTMENT ;
    PORT
      LAYER M4 ;
      RECT 0.000 19.248 0.024 19.272 ;
    END
  END rd_out_A[27]
  PIN rd_out_B[27]
    DIRECTION OUTPUT ;
    USE SIGNAL ;
    SHAPE ABUTMENT ;
    PORT
      LAYER M4 ;
      RECT 51.656 19.248 51.680 19.272 ;
    END
  END rd_out_B[27]
  PIN rd_out_A[28]
    DIRECTION OUTPUT ;
    USE SIGNAL ;
    SHAPE ABUTMENT ;
    PORT
      LAYER M4 ;
      RECT 0.000 19.440 0.024 19.464 ;
    END
  END rd_out_A[28]
  PIN rd_out_B[28]
    DIRECTION OUTPUT ;
    USE SIGNAL ;
    SHAPE ABUTMENT ;
    PORT
      LAYER M4 ;
      RECT 51.656 19.440 51.680 19.464 ;
    END
  END rd_out_B[28]
  PIN rd_out_A[29]
    DIRECTION OUTPUT ;
    USE SIGNAL ;
    SHAPE ABUTMENT ;
    PORT
      LAYER M4 ;
      RECT 0.000 19.632 0.024 19.656 ;
    END
  END rd_out_A[29]
  PIN rd_out_B[29]
    DIRECTION OUTPUT ;
    USE SIGNAL ;
    SHAPE ABUTMENT ;
    PORT
      LAYER M4 ;
      RECT 51.656 19.632 51.680 19.656 ;
    END
  END rd_out_B[29]
  PIN rd_out_A[30]
    DIRECTION OUTPUT ;
    USE SIGNAL ;
    SHAPE ABUTMENT ;
    PORT
      LAYER M4 ;
      RECT 0.000 19.824 0.024 19.848 ;
    END
  END rd_out_A[30]
  PIN rd_out_B[30]
    DIRECTION OUTPUT ;
    USE SIGNAL ;
    SHAPE ABUTMENT ;
    PORT
      LAYER M4 ;
      RECT 51.656 19.824 51.680 19.848 ;
    END
  END rd_out_B[30]
  PIN rd_out_A[31]
    DIRECTION OUTPUT ;
    USE SIGNAL ;
    SHAPE ABUTMENT ;
    PORT
      LAYER M4 ;
      RECT 0.000 20.016 0.024 20.040 ;
    END
  END rd_out_A[31]
  PIN rd_out_B[31]
    DIRECTION OUTPUT ;
    USE SIGNAL ;
    SHAPE ABUTMENT ;
    PORT
      LAYER M4 ;
      RECT 51.656 20.016 51.680 20.040 ;
    END
  END rd_out_B[31]
  PIN rd_out_A[32]
    DIRECTION OUTPUT ;
    USE SIGNAL ;
    SHAPE ABUTMENT ;
    PORT
      LAYER M4 ;
      RECT 0.000 20.208 0.024 20.232 ;
    END
  END rd_out_A[32]
  PIN rd_out_B[32]
    DIRECTION OUTPUT ;
    USE SIGNAL ;
    SHAPE ABUTMENT ;
    PORT
      LAYER M4 ;
      RECT 51.656 20.208 51.680 20.232 ;
    END
  END rd_out_B[32]
  PIN rd_out_A[33]
    DIRECTION OUTPUT ;
    USE SIGNAL ;
    SHAPE ABUTMENT ;
    PORT
      LAYER M4 ;
      RECT 0.000 20.400 0.024 20.424 ;
    END
  END rd_out_A[33]
  PIN rd_out_B[33]
    DIRECTION OUTPUT ;
    USE SIGNAL ;
    SHAPE ABUTMENT ;
    PORT
      LAYER M4 ;
      RECT 51.656 20.400 51.680 20.424 ;
    END
  END rd_out_B[33]
  PIN rd_out_A[34]
    DIRECTION OUTPUT ;
    USE SIGNAL ;
    SHAPE ABUTMENT ;
    PORT
      LAYER M4 ;
      RECT 0.000 20.592 0.024 20.616 ;
    END
  END rd_out_A[34]
  PIN rd_out_B[34]
    DIRECTION OUTPUT ;
    USE SIGNAL ;
    SHAPE ABUTMENT ;
    PORT
      LAYER M4 ;
      RECT 51.656 20.592 51.680 20.616 ;
    END
  END rd_out_B[34]
  PIN rd_out_A[35]
    DIRECTION OUTPUT ;
    USE SIGNAL ;
    SHAPE ABUTMENT ;
    PORT
      LAYER M4 ;
      RECT 0.000 20.784 0.024 20.808 ;
    END
  END rd_out_A[35]
  PIN rd_out_B[35]
    DIRECTION OUTPUT ;
    USE SIGNAL ;
    SHAPE ABUTMENT ;
    PORT
      LAYER M4 ;
      RECT 51.656 20.784 51.680 20.808 ;
    END
  END rd_out_B[35]
  PIN rd_out_A[36]
    DIRECTION OUTPUT ;
    USE SIGNAL ;
    SHAPE ABUTMENT ;
    PORT
      LAYER M4 ;
      RECT 0.000 20.976 0.024 21.000 ;
    END
  END rd_out_A[36]
  PIN rd_out_B[36]
    DIRECTION OUTPUT ;
    USE SIGNAL ;
    SHAPE ABUTMENT ;
    PORT
      LAYER M4 ;
      RECT 51.656 20.976 51.680 21.000 ;
    END
  END rd_out_B[36]
  PIN rd_out_A[37]
    DIRECTION OUTPUT ;
    USE SIGNAL ;
    SHAPE ABUTMENT ;
    PORT
      LAYER M4 ;
      RECT 0.000 21.168 0.024 21.192 ;
    END
  END rd_out_A[37]
  PIN rd_out_B[37]
    DIRECTION OUTPUT ;
    USE SIGNAL ;
    SHAPE ABUTMENT ;
    PORT
      LAYER M4 ;
      RECT 51.656 21.168 51.680 21.192 ;
    END
  END rd_out_B[37]
  PIN rd_out_A[38]
    DIRECTION OUTPUT ;
    USE SIGNAL ;
    SHAPE ABUTMENT ;
    PORT
      LAYER M4 ;
      RECT 0.000 21.360 0.024 21.384 ;
    END
  END rd_out_A[38]
  PIN rd_out_B[38]
    DIRECTION OUTPUT ;
    USE SIGNAL ;
    SHAPE ABUTMENT ;
    PORT
      LAYER M4 ;
      RECT 51.656 21.360 51.680 21.384 ;
    END
  END rd_out_B[38]
  PIN rd_out_A[39]
    DIRECTION OUTPUT ;
    USE SIGNAL ;
    SHAPE ABUTMENT ;
    PORT
      LAYER M4 ;
      RECT 0.000 21.552 0.024 21.576 ;
    END
  END rd_out_A[39]
  PIN rd_out_B[39]
    DIRECTION OUTPUT ;
    USE SIGNAL ;
    SHAPE ABUTMENT ;
    PORT
      LAYER M4 ;
      RECT 51.656 21.552 51.680 21.576 ;
    END
  END rd_out_B[39]
  PIN rd_out_A[40]
    DIRECTION OUTPUT ;
    USE SIGNAL ;
    SHAPE ABUTMENT ;
    PORT
      LAYER M4 ;
      RECT 0.000 21.744 0.024 21.768 ;
    END
  END rd_out_A[40]
  PIN rd_out_B[40]
    DIRECTION OUTPUT ;
    USE SIGNAL ;
    SHAPE ABUTMENT ;
    PORT
      LAYER M4 ;
      RECT 51.656 21.744 51.680 21.768 ;
    END
  END rd_out_B[40]
  PIN rd_out_A[41]
    DIRECTION OUTPUT ;
    USE SIGNAL ;
    SHAPE ABUTMENT ;
    PORT
      LAYER M4 ;
      RECT 0.000 21.936 0.024 21.960 ;
    END
  END rd_out_A[41]
  PIN rd_out_B[41]
    DIRECTION OUTPUT ;
    USE SIGNAL ;
    SHAPE ABUTMENT ;
    PORT
      LAYER M4 ;
      RECT 51.656 21.936 51.680 21.960 ;
    END
  END rd_out_B[41]
  PIN rd_out_A[42]
    DIRECTION OUTPUT ;
    USE SIGNAL ;
    SHAPE ABUTMENT ;
    PORT
      LAYER M4 ;
      RECT 0.000 22.128 0.024 22.152 ;
    END
  END rd_out_A[42]
  PIN rd_out_B[42]
    DIRECTION OUTPUT ;
    USE SIGNAL ;
    SHAPE ABUTMENT ;
    PORT
      LAYER M4 ;
      RECT 51.656 22.128 51.680 22.152 ;
    END
  END rd_out_B[42]
  PIN rd_out_A[43]
    DIRECTION OUTPUT ;
    USE SIGNAL ;
    SHAPE ABUTMENT ;
    PORT
      LAYER M4 ;
      RECT 0.000 22.320 0.024 22.344 ;
    END
  END rd_out_A[43]
  PIN rd_out_B[43]
    DIRECTION OUTPUT ;
    USE SIGNAL ;
    SHAPE ABUTMENT ;
    PORT
      LAYER M4 ;
      RECT 51.656 22.320 51.680 22.344 ;
    END
  END rd_out_B[43]
  PIN rd_out_A[44]
    DIRECTION OUTPUT ;
    USE SIGNAL ;
    SHAPE ABUTMENT ;
    PORT
      LAYER M4 ;
      RECT 0.000 22.512 0.024 22.536 ;
    END
  END rd_out_A[44]
  PIN rd_out_B[44]
    DIRECTION OUTPUT ;
    USE SIGNAL ;
    SHAPE ABUTMENT ;
    PORT
      LAYER M4 ;
      RECT 51.656 22.512 51.680 22.536 ;
    END
  END rd_out_B[44]
  PIN rd_out_A[45]
    DIRECTION OUTPUT ;
    USE SIGNAL ;
    SHAPE ABUTMENT ;
    PORT
      LAYER M4 ;
      RECT 0.000 22.704 0.024 22.728 ;
    END
  END rd_out_A[45]
  PIN rd_out_B[45]
    DIRECTION OUTPUT ;
    USE SIGNAL ;
    SHAPE ABUTMENT ;
    PORT
      LAYER M4 ;
      RECT 51.656 22.704 51.680 22.728 ;
    END
  END rd_out_B[45]
  PIN rd_out_A[46]
    DIRECTION OUTPUT ;
    USE SIGNAL ;
    SHAPE ABUTMENT ;
    PORT
      LAYER M4 ;
      RECT 0.000 22.896 0.024 22.920 ;
    END
  END rd_out_A[46]
  PIN rd_out_B[46]
    DIRECTION OUTPUT ;
    USE SIGNAL ;
    SHAPE ABUTMENT ;
    PORT
      LAYER M4 ;
      RECT 51.656 22.896 51.680 22.920 ;
    END
  END rd_out_B[46]
  PIN rd_out_A[47]
    DIRECTION OUTPUT ;
    USE SIGNAL ;
    SHAPE ABUTMENT ;
    PORT
      LAYER M4 ;
      RECT 0.000 23.088 0.024 23.112 ;
    END
  END rd_out_A[47]
  PIN rd_out_B[47]
    DIRECTION OUTPUT ;
    USE SIGNAL ;
    SHAPE ABUTMENT ;
    PORT
      LAYER M4 ;
      RECT 51.656 23.088 51.680 23.112 ;
    END
  END rd_out_B[47]
  PIN rd_out_A[48]
    DIRECTION OUTPUT ;
    USE SIGNAL ;
    SHAPE ABUTMENT ;
    PORT
      LAYER M4 ;
      RECT 0.000 23.280 0.024 23.304 ;
    END
  END rd_out_A[48]
  PIN rd_out_B[48]
    DIRECTION OUTPUT ;
    USE SIGNAL ;
    SHAPE ABUTMENT ;
    PORT
      LAYER M4 ;
      RECT 51.656 23.280 51.680 23.304 ;
    END
  END rd_out_B[48]
  PIN rd_out_A[49]
    DIRECTION OUTPUT ;
    USE SIGNAL ;
    SHAPE ABUTMENT ;
    PORT
      LAYER M4 ;
      RECT 0.000 23.472 0.024 23.496 ;
    END
  END rd_out_A[49]
  PIN rd_out_B[49]
    DIRECTION OUTPUT ;
    USE SIGNAL ;
    SHAPE ABUTMENT ;
    PORT
      LAYER M4 ;
      RECT 51.656 23.472 51.680 23.496 ;
    END
  END rd_out_B[49]
  PIN rd_out_A[50]
    DIRECTION OUTPUT ;
    USE SIGNAL ;
    SHAPE ABUTMENT ;
    PORT
      LAYER M4 ;
      RECT 0.000 23.664 0.024 23.688 ;
    END
  END rd_out_A[50]
  PIN rd_out_B[50]
    DIRECTION OUTPUT ;
    USE SIGNAL ;
    SHAPE ABUTMENT ;
    PORT
      LAYER M4 ;
      RECT 51.656 23.664 51.680 23.688 ;
    END
  END rd_out_B[50]
  PIN rd_out_A[51]
    DIRECTION OUTPUT ;
    USE SIGNAL ;
    SHAPE ABUTMENT ;
    PORT
      LAYER M4 ;
      RECT 0.000 23.856 0.024 23.880 ;
    END
  END rd_out_A[51]
  PIN rd_out_B[51]
    DIRECTION OUTPUT ;
    USE SIGNAL ;
    SHAPE ABUTMENT ;
    PORT
      LAYER M4 ;
      RECT 51.656 23.856 51.680 23.880 ;
    END
  END rd_out_B[51]
  PIN rd_out_A[52]
    DIRECTION OUTPUT ;
    USE SIGNAL ;
    SHAPE ABUTMENT ;
    PORT
      LAYER M4 ;
      RECT 0.000 24.048 0.024 24.072 ;
    END
  END rd_out_A[52]
  PIN rd_out_B[52]
    DIRECTION OUTPUT ;
    USE SIGNAL ;
    SHAPE ABUTMENT ;
    PORT
      LAYER M4 ;
      RECT 51.656 24.048 51.680 24.072 ;
    END
  END rd_out_B[52]
  PIN rd_out_A[53]
    DIRECTION OUTPUT ;
    USE SIGNAL ;
    SHAPE ABUTMENT ;
    PORT
      LAYER M4 ;
      RECT 0.000 24.240 0.024 24.264 ;
    END
  END rd_out_A[53]
  PIN rd_out_B[53]
    DIRECTION OUTPUT ;
    USE SIGNAL ;
    SHAPE ABUTMENT ;
    PORT
      LAYER M4 ;
      RECT 51.656 24.240 51.680 24.264 ;
    END
  END rd_out_B[53]
  PIN rd_out_A[54]
    DIRECTION OUTPUT ;
    USE SIGNAL ;
    SHAPE ABUTMENT ;
    PORT
      LAYER M4 ;
      RECT 0.000 24.432 0.024 24.456 ;
    END
  END rd_out_A[54]
  PIN rd_out_B[54]
    DIRECTION OUTPUT ;
    USE SIGNAL ;
    SHAPE ABUTMENT ;
    PORT
      LAYER M4 ;
      RECT 51.656 24.432 51.680 24.456 ;
    END
  END rd_out_B[54]
  PIN rd_out_A[55]
    DIRECTION OUTPUT ;
    USE SIGNAL ;
    SHAPE ABUTMENT ;
    PORT
      LAYER M4 ;
      RECT 0.000 24.624 0.024 24.648 ;
    END
  END rd_out_A[55]
  PIN rd_out_B[55]
    DIRECTION OUTPUT ;
    USE SIGNAL ;
    SHAPE ABUTMENT ;
    PORT
      LAYER M4 ;
      RECT 51.656 24.624 51.680 24.648 ;
    END
  END rd_out_B[55]
  PIN rd_out_A[56]
    DIRECTION OUTPUT ;
    USE SIGNAL ;
    SHAPE ABUTMENT ;
    PORT
      LAYER M4 ;
      RECT 0.000 24.816 0.024 24.840 ;
    END
  END rd_out_A[56]
  PIN rd_out_B[56]
    DIRECTION OUTPUT ;
    USE SIGNAL ;
    SHAPE ABUTMENT ;
    PORT
      LAYER M4 ;
      RECT 51.656 24.816 51.680 24.840 ;
    END
  END rd_out_B[56]
  PIN rd_out_A[57]
    DIRECTION OUTPUT ;
    USE SIGNAL ;
    SHAPE ABUTMENT ;
    PORT
      LAYER M4 ;
      RECT 0.000 25.008 0.024 25.032 ;
    END
  END rd_out_A[57]
  PIN rd_out_B[57]
    DIRECTION OUTPUT ;
    USE SIGNAL ;
    SHAPE ABUTMENT ;
    PORT
      LAYER M4 ;
      RECT 51.656 25.008 51.680 25.032 ;
    END
  END rd_out_B[57]
  PIN rd_out_A[58]
    DIRECTION OUTPUT ;
    USE SIGNAL ;
    SHAPE ABUTMENT ;
    PORT
      LAYER M4 ;
      RECT 0.000 25.200 0.024 25.224 ;
    END
  END rd_out_A[58]
  PIN rd_out_B[58]
    DIRECTION OUTPUT ;
    USE SIGNAL ;
    SHAPE ABUTMENT ;
    PORT
      LAYER M4 ;
      RECT 51.656 25.200 51.680 25.224 ;
    END
  END rd_out_B[58]
  PIN rd_out_A[59]
    DIRECTION OUTPUT ;
    USE SIGNAL ;
    SHAPE ABUTMENT ;
    PORT
      LAYER M4 ;
      RECT 0.000 25.392 0.024 25.416 ;
    END
  END rd_out_A[59]
  PIN rd_out_B[59]
    DIRECTION OUTPUT ;
    USE SIGNAL ;
    SHAPE ABUTMENT ;
    PORT
      LAYER M4 ;
      RECT 51.656 25.392 51.680 25.416 ;
    END
  END rd_out_B[59]
  PIN rd_out_A[60]
    DIRECTION OUTPUT ;
    USE SIGNAL ;
    SHAPE ABUTMENT ;
    PORT
      LAYER M4 ;
      RECT 0.000 25.584 0.024 25.608 ;
    END
  END rd_out_A[60]
  PIN rd_out_B[60]
    DIRECTION OUTPUT ;
    USE SIGNAL ;
    SHAPE ABUTMENT ;
    PORT
      LAYER M4 ;
      RECT 51.656 25.584 51.680 25.608 ;
    END
  END rd_out_B[60]
  PIN rd_out_A[61]
    DIRECTION OUTPUT ;
    USE SIGNAL ;
    SHAPE ABUTMENT ;
    PORT
      LAYER M4 ;
      RECT 0.000 25.776 0.024 25.800 ;
    END
  END rd_out_A[61]
  PIN rd_out_B[61]
    DIRECTION OUTPUT ;
    USE SIGNAL ;
    SHAPE ABUTMENT ;
    PORT
      LAYER M4 ;
      RECT 51.656 25.776 51.680 25.800 ;
    END
  END rd_out_B[61]
  PIN rd_out_A[62]
    DIRECTION OUTPUT ;
    USE SIGNAL ;
    SHAPE ABUTMENT ;
    PORT
      LAYER M4 ;
      RECT 0.000 25.968 0.024 25.992 ;
    END
  END rd_out_A[62]
  PIN rd_out_B[62]
    DIRECTION OUTPUT ;
    USE SIGNAL ;
    SHAPE ABUTMENT ;
    PORT
      LAYER M4 ;
      RECT 51.656 25.968 51.680 25.992 ;
    END
  END rd_out_B[62]
  PIN rd_out_A[63]
    DIRECTION OUTPUT ;
    USE SIGNAL ;
    SHAPE ABUTMENT ;
    PORT
      LAYER M4 ;
      RECT 0.000 26.160 0.024 26.184 ;
    END
  END rd_out_A[63]
  PIN rd_out_B[63]
    DIRECTION OUTPUT ;
    USE SIGNAL ;
    SHAPE ABUTMENT ;
    PORT
      LAYER M4 ;
      RECT 51.656 26.160 51.680 26.184 ;
    END
  END rd_out_B[63]
  PIN wd_in_A[0]
    DIRECTION INPUT ;
    USE SIGNAL ;
    SHAPE ABUTMENT ;
    PORT
      LAYER M4 ;
      RECT 0.000 28.080 0.024 28.104 ;
    END
  END wd_in_A[0]
  PIN wd_in_B[0]
    DIRECTION INPUT ;
    USE SIGNAL ;
    SHAPE ABUTMENT ;
    PORT
      LAYER M4 ;
      RECT 51.656 28.080 51.680 28.104 ;
    END
  END wd_in_B[0]
  PIN wd_in_A[1]
    DIRECTION INPUT ;
    USE SIGNAL ;
    SHAPE ABUTMENT ;
    PORT
      LAYER M4 ;
      RECT 0.000 28.272 0.024 28.296 ;
    END
  END wd_in_A[1]
  PIN wd_in_B[1]
    DIRECTION INPUT ;
    USE SIGNAL ;
    SHAPE ABUTMENT ;
    PORT
      LAYER M4 ;
      RECT 51.656 28.272 51.680 28.296 ;
    END
  END wd_in_B[1]
  PIN wd_in_A[2]
    DIRECTION INPUT ;
    USE SIGNAL ;
    SHAPE ABUTMENT ;
    PORT
      LAYER M4 ;
      RECT 0.000 28.464 0.024 28.488 ;
    END
  END wd_in_A[2]
  PIN wd_in_B[2]
    DIRECTION INPUT ;
    USE SIGNAL ;
    SHAPE ABUTMENT ;
    PORT
      LAYER M4 ;
      RECT 51.656 28.464 51.680 28.488 ;
    END
  END wd_in_B[2]
  PIN wd_in_A[3]
    DIRECTION INPUT ;
    USE SIGNAL ;
    SHAPE ABUTMENT ;
    PORT
      LAYER M4 ;
      RECT 0.000 28.656 0.024 28.680 ;
    END
  END wd_in_A[3]
  PIN wd_in_B[3]
    DIRECTION INPUT ;
    USE SIGNAL ;
    SHAPE ABUTMENT ;
    PORT
      LAYER M4 ;
      RECT 51.656 28.656 51.680 28.680 ;
    END
  END wd_in_B[3]
  PIN wd_in_A[4]
    DIRECTION INPUT ;
    USE SIGNAL ;
    SHAPE ABUTMENT ;
    PORT
      LAYER M4 ;
      RECT 0.000 28.848 0.024 28.872 ;
    END
  END wd_in_A[4]
  PIN wd_in_B[4]
    DIRECTION INPUT ;
    USE SIGNAL ;
    SHAPE ABUTMENT ;
    PORT
      LAYER M4 ;
      RECT 51.656 28.848 51.680 28.872 ;
    END
  END wd_in_B[4]
  PIN wd_in_A[5]
    DIRECTION INPUT ;
    USE SIGNAL ;
    SHAPE ABUTMENT ;
    PORT
      LAYER M4 ;
      RECT 0.000 29.040 0.024 29.064 ;
    END
  END wd_in_A[5]
  PIN wd_in_B[5]
    DIRECTION INPUT ;
    USE SIGNAL ;
    SHAPE ABUTMENT ;
    PORT
      LAYER M4 ;
      RECT 51.656 29.040 51.680 29.064 ;
    END
  END wd_in_B[5]
  PIN wd_in_A[6]
    DIRECTION INPUT ;
    USE SIGNAL ;
    SHAPE ABUTMENT ;
    PORT
      LAYER M4 ;
      RECT 0.000 29.232 0.024 29.256 ;
    END
  END wd_in_A[6]
  PIN wd_in_B[6]
    DIRECTION INPUT ;
    USE SIGNAL ;
    SHAPE ABUTMENT ;
    PORT
      LAYER M4 ;
      RECT 51.656 29.232 51.680 29.256 ;
    END
  END wd_in_B[6]
  PIN wd_in_A[7]
    DIRECTION INPUT ;
    USE SIGNAL ;
    SHAPE ABUTMENT ;
    PORT
      LAYER M4 ;
      RECT 0.000 29.424 0.024 29.448 ;
    END
  END wd_in_A[7]
  PIN wd_in_B[7]
    DIRECTION INPUT ;
    USE SIGNAL ;
    SHAPE ABUTMENT ;
    PORT
      LAYER M4 ;
      RECT 51.656 29.424 51.680 29.448 ;
    END
  END wd_in_B[7]
  PIN wd_in_A[8]
    DIRECTION INPUT ;
    USE SIGNAL ;
    SHAPE ABUTMENT ;
    PORT
      LAYER M4 ;
      RECT 0.000 29.616 0.024 29.640 ;
    END
  END wd_in_A[8]
  PIN wd_in_B[8]
    DIRECTION INPUT ;
    USE SIGNAL ;
    SHAPE ABUTMENT ;
    PORT
      LAYER M4 ;
      RECT 51.656 29.616 51.680 29.640 ;
    END
  END wd_in_B[8]
  PIN wd_in_A[9]
    DIRECTION INPUT ;
    USE SIGNAL ;
    SHAPE ABUTMENT ;
    PORT
      LAYER M4 ;
      RECT 0.000 29.808 0.024 29.832 ;
    END
  END wd_in_A[9]
  PIN wd_in_B[9]
    DIRECTION INPUT ;
    USE SIGNAL ;
    SHAPE ABUTMENT ;
    PORT
      LAYER M4 ;
      RECT 51.656 29.808 51.680 29.832 ;
    END
  END wd_in_B[9]
  PIN wd_in_A[10]
    DIRECTION INPUT ;
    USE SIGNAL ;
    SHAPE ABUTMENT ;
    PORT
      LAYER M4 ;
      RECT 0.000 30.000 0.024 30.024 ;
    END
  END wd_in_A[10]
  PIN wd_in_B[10]
    DIRECTION INPUT ;
    USE SIGNAL ;
    SHAPE ABUTMENT ;
    PORT
      LAYER M4 ;
      RECT 51.656 30.000 51.680 30.024 ;
    END
  END wd_in_B[10]
  PIN wd_in_A[11]
    DIRECTION INPUT ;
    USE SIGNAL ;
    SHAPE ABUTMENT ;
    PORT
      LAYER M4 ;
      RECT 0.000 30.192 0.024 30.216 ;
    END
  END wd_in_A[11]
  PIN wd_in_B[11]
    DIRECTION INPUT ;
    USE SIGNAL ;
    SHAPE ABUTMENT ;
    PORT
      LAYER M4 ;
      RECT 51.656 30.192 51.680 30.216 ;
    END
  END wd_in_B[11]
  PIN wd_in_A[12]
    DIRECTION INPUT ;
    USE SIGNAL ;
    SHAPE ABUTMENT ;
    PORT
      LAYER M4 ;
      RECT 0.000 30.384 0.024 30.408 ;
    END
  END wd_in_A[12]
  PIN wd_in_B[12]
    DIRECTION INPUT ;
    USE SIGNAL ;
    SHAPE ABUTMENT ;
    PORT
      LAYER M4 ;
      RECT 51.656 30.384 51.680 30.408 ;
    END
  END wd_in_B[12]
  PIN wd_in_A[13]
    DIRECTION INPUT ;
    USE SIGNAL ;
    SHAPE ABUTMENT ;
    PORT
      LAYER M4 ;
      RECT 0.000 30.576 0.024 30.600 ;
    END
  END wd_in_A[13]
  PIN wd_in_B[13]
    DIRECTION INPUT ;
    USE SIGNAL ;
    SHAPE ABUTMENT ;
    PORT
      LAYER M4 ;
      RECT 51.656 30.576 51.680 30.600 ;
    END
  END wd_in_B[13]
  PIN wd_in_A[14]
    DIRECTION INPUT ;
    USE SIGNAL ;
    SHAPE ABUTMENT ;
    PORT
      LAYER M4 ;
      RECT 0.000 30.768 0.024 30.792 ;
    END
  END wd_in_A[14]
  PIN wd_in_B[14]
    DIRECTION INPUT ;
    USE SIGNAL ;
    SHAPE ABUTMENT ;
    PORT
      LAYER M4 ;
      RECT 51.656 30.768 51.680 30.792 ;
    END
  END wd_in_B[14]
  PIN wd_in_A[15]
    DIRECTION INPUT ;
    USE SIGNAL ;
    SHAPE ABUTMENT ;
    PORT
      LAYER M4 ;
      RECT 0.000 30.960 0.024 30.984 ;
    END
  END wd_in_A[15]
  PIN wd_in_B[15]
    DIRECTION INPUT ;
    USE SIGNAL ;
    SHAPE ABUTMENT ;
    PORT
      LAYER M4 ;
      RECT 51.656 30.960 51.680 30.984 ;
    END
  END wd_in_B[15]
  PIN wd_in_A[16]
    DIRECTION INPUT ;
    USE SIGNAL ;
    SHAPE ABUTMENT ;
    PORT
      LAYER M4 ;
      RECT 0.000 31.152 0.024 31.176 ;
    END
  END wd_in_A[16]
  PIN wd_in_B[16]
    DIRECTION INPUT ;
    USE SIGNAL ;
    SHAPE ABUTMENT ;
    PORT
      LAYER M4 ;
      RECT 51.656 31.152 51.680 31.176 ;
    END
  END wd_in_B[16]
  PIN wd_in_A[17]
    DIRECTION INPUT ;
    USE SIGNAL ;
    SHAPE ABUTMENT ;
    PORT
      LAYER M4 ;
      RECT 0.000 31.344 0.024 31.368 ;
    END
  END wd_in_A[17]
  PIN wd_in_B[17]
    DIRECTION INPUT ;
    USE SIGNAL ;
    SHAPE ABUTMENT ;
    PORT
      LAYER M4 ;
      RECT 51.656 31.344 51.680 31.368 ;
    END
  END wd_in_B[17]
  PIN wd_in_A[18]
    DIRECTION INPUT ;
    USE SIGNAL ;
    SHAPE ABUTMENT ;
    PORT
      LAYER M4 ;
      RECT 0.000 31.536 0.024 31.560 ;
    END
  END wd_in_A[18]
  PIN wd_in_B[18]
    DIRECTION INPUT ;
    USE SIGNAL ;
    SHAPE ABUTMENT ;
    PORT
      LAYER M4 ;
      RECT 51.656 31.536 51.680 31.560 ;
    END
  END wd_in_B[18]
  PIN wd_in_A[19]
    DIRECTION INPUT ;
    USE SIGNAL ;
    SHAPE ABUTMENT ;
    PORT
      LAYER M4 ;
      RECT 0.000 31.728 0.024 31.752 ;
    END
  END wd_in_A[19]
  PIN wd_in_B[19]
    DIRECTION INPUT ;
    USE SIGNAL ;
    SHAPE ABUTMENT ;
    PORT
      LAYER M4 ;
      RECT 51.656 31.728 51.680 31.752 ;
    END
  END wd_in_B[19]
  PIN wd_in_A[20]
    DIRECTION INPUT ;
    USE SIGNAL ;
    SHAPE ABUTMENT ;
    PORT
      LAYER M4 ;
      RECT 0.000 31.920 0.024 31.944 ;
    END
  END wd_in_A[20]
  PIN wd_in_B[20]
    DIRECTION INPUT ;
    USE SIGNAL ;
    SHAPE ABUTMENT ;
    PORT
      LAYER M4 ;
      RECT 51.656 31.920 51.680 31.944 ;
    END
  END wd_in_B[20]
  PIN wd_in_A[21]
    DIRECTION INPUT ;
    USE SIGNAL ;
    SHAPE ABUTMENT ;
    PORT
      LAYER M4 ;
      RECT 0.000 32.112 0.024 32.136 ;
    END
  END wd_in_A[21]
  PIN wd_in_B[21]
    DIRECTION INPUT ;
    USE SIGNAL ;
    SHAPE ABUTMENT ;
    PORT
      LAYER M4 ;
      RECT 51.656 32.112 51.680 32.136 ;
    END
  END wd_in_B[21]
  PIN wd_in_A[22]
    DIRECTION INPUT ;
    USE SIGNAL ;
    SHAPE ABUTMENT ;
    PORT
      LAYER M4 ;
      RECT 0.000 32.304 0.024 32.328 ;
    END
  END wd_in_A[22]
  PIN wd_in_B[22]
    DIRECTION INPUT ;
    USE SIGNAL ;
    SHAPE ABUTMENT ;
    PORT
      LAYER M4 ;
      RECT 51.656 32.304 51.680 32.328 ;
    END
  END wd_in_B[22]
  PIN wd_in_A[23]
    DIRECTION INPUT ;
    USE SIGNAL ;
    SHAPE ABUTMENT ;
    PORT
      LAYER M4 ;
      RECT 0.000 32.496 0.024 32.520 ;
    END
  END wd_in_A[23]
  PIN wd_in_B[23]
    DIRECTION INPUT ;
    USE SIGNAL ;
    SHAPE ABUTMENT ;
    PORT
      LAYER M4 ;
      RECT 51.656 32.496 51.680 32.520 ;
    END
  END wd_in_B[23]
  PIN wd_in_A[24]
    DIRECTION INPUT ;
    USE SIGNAL ;
    SHAPE ABUTMENT ;
    PORT
      LAYER M4 ;
      RECT 0.000 32.688 0.024 32.712 ;
    END
  END wd_in_A[24]
  PIN wd_in_B[24]
    DIRECTION INPUT ;
    USE SIGNAL ;
    SHAPE ABUTMENT ;
    PORT
      LAYER M4 ;
      RECT 51.656 32.688 51.680 32.712 ;
    END
  END wd_in_B[24]
  PIN wd_in_A[25]
    DIRECTION INPUT ;
    USE SIGNAL ;
    SHAPE ABUTMENT ;
    PORT
      LAYER M4 ;
      RECT 0.000 32.880 0.024 32.904 ;
    END
  END wd_in_A[25]
  PIN wd_in_B[25]
    DIRECTION INPUT ;
    USE SIGNAL ;
    SHAPE ABUTMENT ;
    PORT
      LAYER M4 ;
      RECT 51.656 32.880 51.680 32.904 ;
    END
  END wd_in_B[25]
  PIN wd_in_A[26]
    DIRECTION INPUT ;
    USE SIGNAL ;
    SHAPE ABUTMENT ;
    PORT
      LAYER M4 ;
      RECT 0.000 33.072 0.024 33.096 ;
    END
  END wd_in_A[26]
  PIN wd_in_B[26]
    DIRECTION INPUT ;
    USE SIGNAL ;
    SHAPE ABUTMENT ;
    PORT
      LAYER M4 ;
      RECT 51.656 33.072 51.680 33.096 ;
    END
  END wd_in_B[26]
  PIN wd_in_A[27]
    DIRECTION INPUT ;
    USE SIGNAL ;
    SHAPE ABUTMENT ;
    PORT
      LAYER M4 ;
      RECT 0.000 33.264 0.024 33.288 ;
    END
  END wd_in_A[27]
  PIN wd_in_B[27]
    DIRECTION INPUT ;
    USE SIGNAL ;
    SHAPE ABUTMENT ;
    PORT
      LAYER M4 ;
      RECT 51.656 33.264 51.680 33.288 ;
    END
  END wd_in_B[27]
  PIN wd_in_A[28]
    DIRECTION INPUT ;
    USE SIGNAL ;
    SHAPE ABUTMENT ;
    PORT
      LAYER M4 ;
      RECT 0.000 33.456 0.024 33.480 ;
    END
  END wd_in_A[28]
  PIN wd_in_B[28]
    DIRECTION INPUT ;
    USE SIGNAL ;
    SHAPE ABUTMENT ;
    PORT
      LAYER M4 ;
      RECT 51.656 33.456 51.680 33.480 ;
    END
  END wd_in_B[28]
  PIN wd_in_A[29]
    DIRECTION INPUT ;
    USE SIGNAL ;
    SHAPE ABUTMENT ;
    PORT
      LAYER M4 ;
      RECT 0.000 33.648 0.024 33.672 ;
    END
  END wd_in_A[29]
  PIN wd_in_B[29]
    DIRECTION INPUT ;
    USE SIGNAL ;
    SHAPE ABUTMENT ;
    PORT
      LAYER M4 ;
      RECT 51.656 33.648 51.680 33.672 ;
    END
  END wd_in_B[29]
  PIN wd_in_A[30]
    DIRECTION INPUT ;
    USE SIGNAL ;
    SHAPE ABUTMENT ;
    PORT
      LAYER M4 ;
      RECT 0.000 33.840 0.024 33.864 ;
    END
  END wd_in_A[30]
  PIN wd_in_B[30]
    DIRECTION INPUT ;
    USE SIGNAL ;
    SHAPE ABUTMENT ;
    PORT
      LAYER M4 ;
      RECT 51.656 33.840 51.680 33.864 ;
    END
  END wd_in_B[30]
  PIN wd_in_A[31]
    DIRECTION INPUT ;
    USE SIGNAL ;
    SHAPE ABUTMENT ;
    PORT
      LAYER M4 ;
      RECT 0.000 34.032 0.024 34.056 ;
    END
  END wd_in_A[31]
  PIN wd_in_B[31]
    DIRECTION INPUT ;
    USE SIGNAL ;
    SHAPE ABUTMENT ;
    PORT
      LAYER M4 ;
      RECT 51.656 34.032 51.680 34.056 ;
    END
  END wd_in_B[31]
  PIN wd_in_A[32]
    DIRECTION INPUT ;
    USE SIGNAL ;
    SHAPE ABUTMENT ;
    PORT
      LAYER M4 ;
      RECT 0.000 34.224 0.024 34.248 ;
    END
  END wd_in_A[32]
  PIN wd_in_B[32]
    DIRECTION INPUT ;
    USE SIGNAL ;
    SHAPE ABUTMENT ;
    PORT
      LAYER M4 ;
      RECT 51.656 34.224 51.680 34.248 ;
    END
  END wd_in_B[32]
  PIN wd_in_A[33]
    DIRECTION INPUT ;
    USE SIGNAL ;
    SHAPE ABUTMENT ;
    PORT
      LAYER M4 ;
      RECT 0.000 34.416 0.024 34.440 ;
    END
  END wd_in_A[33]
  PIN wd_in_B[33]
    DIRECTION INPUT ;
    USE SIGNAL ;
    SHAPE ABUTMENT ;
    PORT
      LAYER M4 ;
      RECT 51.656 34.416 51.680 34.440 ;
    END
  END wd_in_B[33]
  PIN wd_in_A[34]
    DIRECTION INPUT ;
    USE SIGNAL ;
    SHAPE ABUTMENT ;
    PORT
      LAYER M4 ;
      RECT 0.000 34.608 0.024 34.632 ;
    END
  END wd_in_A[34]
  PIN wd_in_B[34]
    DIRECTION INPUT ;
    USE SIGNAL ;
    SHAPE ABUTMENT ;
    PORT
      LAYER M4 ;
      RECT 51.656 34.608 51.680 34.632 ;
    END
  END wd_in_B[34]
  PIN wd_in_A[35]
    DIRECTION INPUT ;
    USE SIGNAL ;
    SHAPE ABUTMENT ;
    PORT
      LAYER M4 ;
      RECT 0.000 34.800 0.024 34.824 ;
    END
  END wd_in_A[35]
  PIN wd_in_B[35]
    DIRECTION INPUT ;
    USE SIGNAL ;
    SHAPE ABUTMENT ;
    PORT
      LAYER M4 ;
      RECT 51.656 34.800 51.680 34.824 ;
    END
  END wd_in_B[35]
  PIN wd_in_A[36]
    DIRECTION INPUT ;
    USE SIGNAL ;
    SHAPE ABUTMENT ;
    PORT
      LAYER M4 ;
      RECT 0.000 34.992 0.024 35.016 ;
    END
  END wd_in_A[36]
  PIN wd_in_B[36]
    DIRECTION INPUT ;
    USE SIGNAL ;
    SHAPE ABUTMENT ;
    PORT
      LAYER M4 ;
      RECT 51.656 34.992 51.680 35.016 ;
    END
  END wd_in_B[36]
  PIN wd_in_A[37]
    DIRECTION INPUT ;
    USE SIGNAL ;
    SHAPE ABUTMENT ;
    PORT
      LAYER M4 ;
      RECT 0.000 35.184 0.024 35.208 ;
    END
  END wd_in_A[37]
  PIN wd_in_B[37]
    DIRECTION INPUT ;
    USE SIGNAL ;
    SHAPE ABUTMENT ;
    PORT
      LAYER M4 ;
      RECT 51.656 35.184 51.680 35.208 ;
    END
  END wd_in_B[37]
  PIN wd_in_A[38]
    DIRECTION INPUT ;
    USE SIGNAL ;
    SHAPE ABUTMENT ;
    PORT
      LAYER M4 ;
      RECT 0.000 35.376 0.024 35.400 ;
    END
  END wd_in_A[38]
  PIN wd_in_B[38]
    DIRECTION INPUT ;
    USE SIGNAL ;
    SHAPE ABUTMENT ;
    PORT
      LAYER M4 ;
      RECT 51.656 35.376 51.680 35.400 ;
    END
  END wd_in_B[38]
  PIN wd_in_A[39]
    DIRECTION INPUT ;
    USE SIGNAL ;
    SHAPE ABUTMENT ;
    PORT
      LAYER M4 ;
      RECT 0.000 35.568 0.024 35.592 ;
    END
  END wd_in_A[39]
  PIN wd_in_B[39]
    DIRECTION INPUT ;
    USE SIGNAL ;
    SHAPE ABUTMENT ;
    PORT
      LAYER M4 ;
      RECT 51.656 35.568 51.680 35.592 ;
    END
  END wd_in_B[39]
  PIN wd_in_A[40]
    DIRECTION INPUT ;
    USE SIGNAL ;
    SHAPE ABUTMENT ;
    PORT
      LAYER M4 ;
      RECT 0.000 35.760 0.024 35.784 ;
    END
  END wd_in_A[40]
  PIN wd_in_B[40]
    DIRECTION INPUT ;
    USE SIGNAL ;
    SHAPE ABUTMENT ;
    PORT
      LAYER M4 ;
      RECT 51.656 35.760 51.680 35.784 ;
    END
  END wd_in_B[40]
  PIN wd_in_A[41]
    DIRECTION INPUT ;
    USE SIGNAL ;
    SHAPE ABUTMENT ;
    PORT
      LAYER M4 ;
      RECT 0.000 35.952 0.024 35.976 ;
    END
  END wd_in_A[41]
  PIN wd_in_B[41]
    DIRECTION INPUT ;
    USE SIGNAL ;
    SHAPE ABUTMENT ;
    PORT
      LAYER M4 ;
      RECT 51.656 35.952 51.680 35.976 ;
    END
  END wd_in_B[41]
  PIN wd_in_A[42]
    DIRECTION INPUT ;
    USE SIGNAL ;
    SHAPE ABUTMENT ;
    PORT
      LAYER M4 ;
      RECT 0.000 36.144 0.024 36.168 ;
    END
  END wd_in_A[42]
  PIN wd_in_B[42]
    DIRECTION INPUT ;
    USE SIGNAL ;
    SHAPE ABUTMENT ;
    PORT
      LAYER M4 ;
      RECT 51.656 36.144 51.680 36.168 ;
    END
  END wd_in_B[42]
  PIN wd_in_A[43]
    DIRECTION INPUT ;
    USE SIGNAL ;
    SHAPE ABUTMENT ;
    PORT
      LAYER M4 ;
      RECT 0.000 36.336 0.024 36.360 ;
    END
  END wd_in_A[43]
  PIN wd_in_B[43]
    DIRECTION INPUT ;
    USE SIGNAL ;
    SHAPE ABUTMENT ;
    PORT
      LAYER M4 ;
      RECT 51.656 36.336 51.680 36.360 ;
    END
  END wd_in_B[43]
  PIN wd_in_A[44]
    DIRECTION INPUT ;
    USE SIGNAL ;
    SHAPE ABUTMENT ;
    PORT
      LAYER M4 ;
      RECT 0.000 36.528 0.024 36.552 ;
    END
  END wd_in_A[44]
  PIN wd_in_B[44]
    DIRECTION INPUT ;
    USE SIGNAL ;
    SHAPE ABUTMENT ;
    PORT
      LAYER M4 ;
      RECT 51.656 36.528 51.680 36.552 ;
    END
  END wd_in_B[44]
  PIN wd_in_A[45]
    DIRECTION INPUT ;
    USE SIGNAL ;
    SHAPE ABUTMENT ;
    PORT
      LAYER M4 ;
      RECT 0.000 36.720 0.024 36.744 ;
    END
  END wd_in_A[45]
  PIN wd_in_B[45]
    DIRECTION INPUT ;
    USE SIGNAL ;
    SHAPE ABUTMENT ;
    PORT
      LAYER M4 ;
      RECT 51.656 36.720 51.680 36.744 ;
    END
  END wd_in_B[45]
  PIN wd_in_A[46]
    DIRECTION INPUT ;
    USE SIGNAL ;
    SHAPE ABUTMENT ;
    PORT
      LAYER M4 ;
      RECT 0.000 36.912 0.024 36.936 ;
    END
  END wd_in_A[46]
  PIN wd_in_B[46]
    DIRECTION INPUT ;
    USE SIGNAL ;
    SHAPE ABUTMENT ;
    PORT
      LAYER M4 ;
      RECT 51.656 36.912 51.680 36.936 ;
    END
  END wd_in_B[46]
  PIN wd_in_A[47]
    DIRECTION INPUT ;
    USE SIGNAL ;
    SHAPE ABUTMENT ;
    PORT
      LAYER M4 ;
      RECT 0.000 37.104 0.024 37.128 ;
    END
  END wd_in_A[47]
  PIN wd_in_B[47]
    DIRECTION INPUT ;
    USE SIGNAL ;
    SHAPE ABUTMENT ;
    PORT
      LAYER M4 ;
      RECT 51.656 37.104 51.680 37.128 ;
    END
  END wd_in_B[47]
  PIN wd_in_A[48]
    DIRECTION INPUT ;
    USE SIGNAL ;
    SHAPE ABUTMENT ;
    PORT
      LAYER M4 ;
      RECT 0.000 37.296 0.024 37.320 ;
    END
  END wd_in_A[48]
  PIN wd_in_B[48]
    DIRECTION INPUT ;
    USE SIGNAL ;
    SHAPE ABUTMENT ;
    PORT
      LAYER M4 ;
      RECT 51.656 37.296 51.680 37.320 ;
    END
  END wd_in_B[48]
  PIN wd_in_A[49]
    DIRECTION INPUT ;
    USE SIGNAL ;
    SHAPE ABUTMENT ;
    PORT
      LAYER M4 ;
      RECT 0.000 37.488 0.024 37.512 ;
    END
  END wd_in_A[49]
  PIN wd_in_B[49]
    DIRECTION INPUT ;
    USE SIGNAL ;
    SHAPE ABUTMENT ;
    PORT
      LAYER M4 ;
      RECT 51.656 37.488 51.680 37.512 ;
    END
  END wd_in_B[49]
  PIN wd_in_A[50]
    DIRECTION INPUT ;
    USE SIGNAL ;
    SHAPE ABUTMENT ;
    PORT
      LAYER M4 ;
      RECT 0.000 37.680 0.024 37.704 ;
    END
  END wd_in_A[50]
  PIN wd_in_B[50]
    DIRECTION INPUT ;
    USE SIGNAL ;
    SHAPE ABUTMENT ;
    PORT
      LAYER M4 ;
      RECT 51.656 37.680 51.680 37.704 ;
    END
  END wd_in_B[50]
  PIN wd_in_A[51]
    DIRECTION INPUT ;
    USE SIGNAL ;
    SHAPE ABUTMENT ;
    PORT
      LAYER M4 ;
      RECT 0.000 37.872 0.024 37.896 ;
    END
  END wd_in_A[51]
  PIN wd_in_B[51]
    DIRECTION INPUT ;
    USE SIGNAL ;
    SHAPE ABUTMENT ;
    PORT
      LAYER M4 ;
      RECT 51.656 37.872 51.680 37.896 ;
    END
  END wd_in_B[51]
  PIN wd_in_A[52]
    DIRECTION INPUT ;
    USE SIGNAL ;
    SHAPE ABUTMENT ;
    PORT
      LAYER M4 ;
      RECT 0.000 38.064 0.024 38.088 ;
    END
  END wd_in_A[52]
  PIN wd_in_B[52]
    DIRECTION INPUT ;
    USE SIGNAL ;
    SHAPE ABUTMENT ;
    PORT
      LAYER M4 ;
      RECT 51.656 38.064 51.680 38.088 ;
    END
  END wd_in_B[52]
  PIN wd_in_A[53]
    DIRECTION INPUT ;
    USE SIGNAL ;
    SHAPE ABUTMENT ;
    PORT
      LAYER M4 ;
      RECT 0.000 38.256 0.024 38.280 ;
    END
  END wd_in_A[53]
  PIN wd_in_B[53]
    DIRECTION INPUT ;
    USE SIGNAL ;
    SHAPE ABUTMENT ;
    PORT
      LAYER M4 ;
      RECT 51.656 38.256 51.680 38.280 ;
    END
  END wd_in_B[53]
  PIN wd_in_A[54]
    DIRECTION INPUT ;
    USE SIGNAL ;
    SHAPE ABUTMENT ;
    PORT
      LAYER M4 ;
      RECT 0.000 38.448 0.024 38.472 ;
    END
  END wd_in_A[54]
  PIN wd_in_B[54]
    DIRECTION INPUT ;
    USE SIGNAL ;
    SHAPE ABUTMENT ;
    PORT
      LAYER M4 ;
      RECT 51.656 38.448 51.680 38.472 ;
    END
  END wd_in_B[54]
  PIN wd_in_A[55]
    DIRECTION INPUT ;
    USE SIGNAL ;
    SHAPE ABUTMENT ;
    PORT
      LAYER M4 ;
      RECT 0.000 38.640 0.024 38.664 ;
    END
  END wd_in_A[55]
  PIN wd_in_B[55]
    DIRECTION INPUT ;
    USE SIGNAL ;
    SHAPE ABUTMENT ;
    PORT
      LAYER M4 ;
      RECT 51.656 38.640 51.680 38.664 ;
    END
  END wd_in_B[55]
  PIN wd_in_A[56]
    DIRECTION INPUT ;
    USE SIGNAL ;
    SHAPE ABUTMENT ;
    PORT
      LAYER M4 ;
      RECT 0.000 38.832 0.024 38.856 ;
    END
  END wd_in_A[56]
  PIN wd_in_B[56]
    DIRECTION INPUT ;
    USE SIGNAL ;
    SHAPE ABUTMENT ;
    PORT
      LAYER M4 ;
      RECT 51.656 38.832 51.680 38.856 ;
    END
  END wd_in_B[56]
  PIN wd_in_A[57]
    DIRECTION INPUT ;
    USE SIGNAL ;
    SHAPE ABUTMENT ;
    PORT
      LAYER M4 ;
      RECT 0.000 39.024 0.024 39.048 ;
    END
  END wd_in_A[57]
  PIN wd_in_B[57]
    DIRECTION INPUT ;
    USE SIGNAL ;
    SHAPE ABUTMENT ;
    PORT
      LAYER M4 ;
      RECT 51.656 39.024 51.680 39.048 ;
    END
  END wd_in_B[57]
  PIN wd_in_A[58]
    DIRECTION INPUT ;
    USE SIGNAL ;
    SHAPE ABUTMENT ;
    PORT
      LAYER M4 ;
      RECT 0.000 39.216 0.024 39.240 ;
    END
  END wd_in_A[58]
  PIN wd_in_B[58]
    DIRECTION INPUT ;
    USE SIGNAL ;
    SHAPE ABUTMENT ;
    PORT
      LAYER M4 ;
      RECT 51.656 39.216 51.680 39.240 ;
    END
  END wd_in_B[58]
  PIN wd_in_A[59]
    DIRECTION INPUT ;
    USE SIGNAL ;
    SHAPE ABUTMENT ;
    PORT
      LAYER M4 ;
      RECT 0.000 39.408 0.024 39.432 ;
    END
  END wd_in_A[59]
  PIN wd_in_B[59]
    DIRECTION INPUT ;
    USE SIGNAL ;
    SHAPE ABUTMENT ;
    PORT
      LAYER M4 ;
      RECT 51.656 39.408 51.680 39.432 ;
    END
  END wd_in_B[59]
  PIN wd_in_A[60]
    DIRECTION INPUT ;
    USE SIGNAL ;
    SHAPE ABUTMENT ;
    PORT
      LAYER M4 ;
      RECT 0.000 39.600 0.024 39.624 ;
    END
  END wd_in_A[60]
  PIN wd_in_B[60]
    DIRECTION INPUT ;
    USE SIGNAL ;
    SHAPE ABUTMENT ;
    PORT
      LAYER M4 ;
      RECT 51.656 39.600 51.680 39.624 ;
    END
  END wd_in_B[60]
  PIN wd_in_A[61]
    DIRECTION INPUT ;
    USE SIGNAL ;
    SHAPE ABUTMENT ;
    PORT
      LAYER M4 ;
      RECT 0.000 39.792 0.024 39.816 ;
    END
  END wd_in_A[61]
  PIN wd_in_B[61]
    DIRECTION INPUT ;
    USE SIGNAL ;
    SHAPE ABUTMENT ;
    PORT
      LAYER M4 ;
      RECT 51.656 39.792 51.680 39.816 ;
    END
  END wd_in_B[61]
  PIN wd_in_A[62]
    DIRECTION INPUT ;
    USE SIGNAL ;
    SHAPE ABUTMENT ;
    PORT
      LAYER M4 ;
      RECT 0.000 39.984 0.024 40.008 ;
    END
  END wd_in_A[62]
  PIN wd_in_B[62]
    DIRECTION INPUT ;
    USE SIGNAL ;
    SHAPE ABUTMENT ;
    PORT
      LAYER M4 ;
      RECT 51.656 39.984 51.680 40.008 ;
    END
  END wd_in_B[62]
  PIN wd_in_A[63]
    DIRECTION INPUT ;
    USE SIGNAL ;
    SHAPE ABUTMENT ;
    PORT
      LAYER M4 ;
      RECT 0.000 40.176 0.024 40.200 ;
    END
  END wd_in_A[63]
  PIN wd_in_B[63]
    DIRECTION INPUT ;
    USE SIGNAL ;
    SHAPE ABUTMENT ;
    PORT
      LAYER M4 ;
      RECT 51.656 40.176 51.680 40.200 ;
    END
  END wd_in_B[63]
  PIN addr_in_A[0]
    DIRECTION INPUT ;
    USE SIGNAL ;
    SHAPE ABUTMENT ;
    PORT
      LAYER M4 ;
      RECT 0.000 42.096 0.024 42.120 ;
    END
  END addr_in_A[0]
  PIN addr_in_B[0]
    DIRECTION INPUT ;
    USE SIGNAL ;
    SHAPE ABUTMENT ;
    PORT
      LAYER M4 ;
      RECT 51.656 42.096 51.680 42.120 ;
    END
  END addr_in_B[0]
  PIN addr_in_A[1]
    DIRECTION INPUT ;
    USE SIGNAL ;
    SHAPE ABUTMENT ;
    PORT
      LAYER M4 ;
      RECT 0.000 42.288 0.024 42.312 ;
    END
  END addr_in_A[1]
  PIN addr_in_B[1]
    DIRECTION INPUT ;
    USE SIGNAL ;
    SHAPE ABUTMENT ;
    PORT
      LAYER M4 ;
      RECT 51.656 42.288 51.680 42.312 ;
    END
  END addr_in_B[1]
  PIN addr_in_A[2]
    DIRECTION INPUT ;
    USE SIGNAL ;
    SHAPE ABUTMENT ;
    PORT
      LAYER M4 ;
      RECT 0.000 42.480 0.024 42.504 ;
    END
  END addr_in_A[2]
  PIN addr_in_B[2]
    DIRECTION INPUT ;
    USE SIGNAL ;
    SHAPE ABUTMENT ;
    PORT
      LAYER M4 ;
      RECT 51.656 42.480 51.680 42.504 ;
    END
  END addr_in_B[2]
  PIN addr_in_A[3]
    DIRECTION INPUT ;
    USE SIGNAL ;
    SHAPE ABUTMENT ;
    PORT
      LAYER M4 ;
      RECT 0.000 42.672 0.024 42.696 ;
    END
  END addr_in_A[3]
  PIN addr_in_B[3]
    DIRECTION INPUT ;
    USE SIGNAL ;
    SHAPE ABUTMENT ;
    PORT
      LAYER M4 ;
      RECT 51.656 42.672 51.680 42.696 ;
    END
  END addr_in_B[3]
  PIN addr_in_A[4]
    DIRECTION INPUT ;
    USE SIGNAL ;
    SHAPE ABUTMENT ;
    PORT
      LAYER M4 ;
      RECT 0.000 42.864 0.024 42.888 ;
    END
  END addr_in_A[4]
  PIN addr_in_B[4]
    DIRECTION INPUT ;
    USE SIGNAL ;
    SHAPE ABUTMENT ;
    PORT
      LAYER M4 ;
      RECT 51.656 42.864 51.680 42.888 ;
    END
  END addr_in_B[4]
  PIN addr_in_A[5]
    DIRECTION INPUT ;
    USE SIGNAL ;
    SHAPE ABUTMENT ;
    PORT
      LAYER M4 ;
      RECT 0.000 43.056 0.024 43.080 ;
    END
  END addr_in_A[5]
  PIN addr_in_B[5]
    DIRECTION INPUT ;
    USE SIGNAL ;
    SHAPE ABUTMENT ;
    PORT
      LAYER M4 ;
      RECT 51.656 43.056 51.680 43.080 ;
    END
  END addr_in_B[5]
  PIN addr_in_A[6]
    DIRECTION INPUT ;
    USE SIGNAL ;
    SHAPE ABUTMENT ;
    PORT
      LAYER M4 ;
      RECT 0.000 43.248 0.024 43.272 ;
    END
  END addr_in_A[6]
  PIN addr_in_B[6]
    DIRECTION INPUT ;
    USE SIGNAL ;
    SHAPE ABUTMENT ;
    PORT
      LAYER M4 ;
      RECT 51.656 43.248 51.680 43.272 ;
    END
  END addr_in_B[6]
  PIN addr_in_A[7]
    DIRECTION INPUT ;
    USE SIGNAL ;
    SHAPE ABUTMENT ;
    PORT
      LAYER M4 ;
      RECT 0.000 43.440 0.024 43.464 ;
    END
  END addr_in_A[7]
  PIN addr_in_B[7]
    DIRECTION INPUT ;
    USE SIGNAL ;
    SHAPE ABUTMENT ;
    PORT
      LAYER M4 ;
      RECT 51.656 43.440 51.680 43.464 ;
    END
  END addr_in_B[7]
  PIN addr_in_A[8]
    DIRECTION INPUT ;
    USE SIGNAL ;
    SHAPE ABUTMENT ;
    PORT
      LAYER M4 ;
      RECT 0.000 43.632 0.024 43.656 ;
    END
  END addr_in_A[8]
  PIN addr_in_B[8]
    DIRECTION INPUT ;
    USE SIGNAL ;
    SHAPE ABUTMENT ;
    PORT
      LAYER M4 ;
      RECT 51.656 43.632 51.680 43.656 ;
    END
  END addr_in_B[8]
  PIN we_in_A
    DIRECTION INPUT ;
    USE SIGNAL ;
    SHAPE ABUTMENT ;
    PORT
      LAYER M4 ;
      RECT 0.000 45.552 0.024 45.576 ;
    END
  END we_in_A
  PIN we_in_B
    DIRECTION INPUT ;
    USE SIGNAL ;
    SHAPE ABUTMENT ;
    PORT
      LAYER M4 ;
      RECT 51.656 45.552 51.680 45.576 ;
    END
  END we_in_B
  PIN ce_in_A
    DIRECTION INPUT ;
    USE SIGNAL ;
    SHAPE ABUTMENT ;
    PORT
      LAYER M4 ;
      RECT 0.000 45.744 0.024 45.768 ;
    END
  END ce_in_A
  PIN clk_A
    DIRECTION INPUT ;
    USE SIGNAL ;
    SHAPE ABUTMENT ;
    PORT
      LAYER M4 ;
      RECT 0.000 45.936 0.024 45.960 ;
    END
  END clk_A
  PIN ce_in_B
    DIRECTION INPUT ;
    USE SIGNAL ;
    SHAPE ABUTMENT ;
    PORT
      LAYER M4 ;
      RECT 0.000 46.128 0.024 46.152 ;
    END
  END ce_in_B
  PIN clk_B
    DIRECTION INPUT ;
    USE SIGNAL ;
    SHAPE ABUTMENT ;
    PORT
      LAYER M4 ;
      RECT 0.000 46.320 0.024 46.344 ;
    END
  END clk_B
  PIN VSS
    DIRECTION INOUT ;
    USE GROUND ;
    PORT
      LAYER M4 ;
      RECT 0.048 0.000 51.632 0.096 ;
      RECT 0.048 0.768 51.632 0.864 ;
      RECT 0.048 1.536 51.632 1.632 ;
      RECT 0.048 2.304 51.632 2.400 ;
      RECT 0.048 3.072 51.632 3.168 ;
      RECT 0.048 3.840 51.632 3.936 ;
      RECT 0.048 4.608 51.632 4.704 ;
      RECT 0.048 5.376 51.632 5.472 ;
      RECT 0.048 6.144 51.632 6.240 ;
      RECT 0.048 6.912 51.632 7.008 ;
      RECT 0.048 7.680 51.632 7.776 ;
      RECT 0.048 8.448 51.632 8.544 ;
      RECT 0.048 9.216 51.632 9.312 ;
      RECT 0.048 9.984 51.632 10.080 ;
      RECT 0.048 10.752 51.632 10.848 ;
      RECT 0.048 11.520 51.632 11.616 ;
      RECT 0.048 12.288 51.632 12.384 ;
      RECT 0.048 13.056 51.632 13.152 ;
      RECT 0.048 13.824 51.632 13.920 ;
      RECT 0.048 14.592 51.632 14.688 ;
      RECT 0.048 15.360 51.632 15.456 ;
      RECT 0.048 16.128 51.632 16.224 ;
      RECT 0.048 16.896 51.632 16.992 ;
      RECT 0.048 17.664 51.632 17.760 ;
      RECT 0.048 18.432 51.632 18.528 ;
      RECT 0.048 19.200 51.632 19.296 ;
      RECT 0.048 19.968 51.632 20.064 ;
      RECT 0.048 20.736 51.632 20.832 ;
      RECT 0.048 21.504 51.632 21.600 ;
      RECT 0.048 22.272 51.632 22.368 ;
      RECT 0.048 23.040 51.632 23.136 ;
      RECT 0.048 23.808 51.632 23.904 ;
      RECT 0.048 24.576 51.632 24.672 ;
      RECT 0.048 25.344 51.632 25.440 ;
      RECT 0.048 26.112 51.632 26.208 ;
      RECT 0.048 26.880 51.632 26.976 ;
      RECT 0.048 27.648 51.632 27.744 ;
      RECT 0.048 28.416 51.632 28.512 ;
      RECT 0.048 29.184 51.632 29.280 ;
      RECT 0.048 29.952 51.632 30.048 ;
      RECT 0.048 30.720 51.632 30.816 ;
      RECT 0.048 31.488 51.632 31.584 ;
      RECT 0.048 32.256 51.632 32.352 ;
      RECT 0.048 33.024 51.632 33.120 ;
      RECT 0.048 33.792 51.632 33.888 ;
      RECT 0.048 34.560 51.632 34.656 ;
      RECT 0.048 35.328 51.632 35.424 ;
      RECT 0.048 36.096 51.632 36.192 ;
      RECT 0.048 36.864 51.632 36.960 ;
      RECT 0.048 37.632 51.632 37.728 ;
      RECT 0.048 38.400 51.632 38.496 ;
      RECT 0.048 39.168 51.632 39.264 ;
      RECT 0.048 39.936 51.632 40.032 ;
      RECT 0.048 40.704 51.632 40.800 ;
      RECT 0.048 41.472 51.632 41.568 ;
      RECT 0.048 42.240 51.632 42.336 ;
      RECT 0.048 43.008 51.632 43.104 ;
      RECT 0.048 43.776 51.632 43.872 ;
      RECT 0.048 44.544 51.632 44.640 ;
      RECT 0.048 45.312 51.632 45.408 ;
      RECT 0.048 46.080 51.632 46.176 ;
    END
  END VSS
  PIN VDD
    DIRECTION INOUT ;
    USE POWER ;
    PORT
      LAYER M4 ;
      RECT 0.048 0.384 51.632 0.480 ;
      RECT 0.048 1.152 51.632 1.248 ;
      RECT 0.048 1.920 51.632 2.016 ;
      RECT 0.048 2.688 51.632 2.784 ;
      RECT 0.048 3.456 51.632 3.552 ;
      RECT 0.048 4.224 51.632 4.320 ;
      RECT 0.048 4.992 51.632 5.088 ;
      RECT 0.048 5.760 51.632 5.856 ;
      RECT 0.048 6.528 51.632 6.624 ;
      RECT 0.048 7.296 51.632 7.392 ;
      RECT 0.048 8.064 51.632 8.160 ;
      RECT 0.048 8.832 51.632 8.928 ;
      RECT 0.048 9.600 51.632 9.696 ;
      RECT 0.048 10.368 51.632 10.464 ;
      RECT 0.048 11.136 51.632 11.232 ;
      RECT 0.048 11.904 51.632 12.000 ;
      RECT 0.048 12.672 51.632 12.768 ;
      RECT 0.048 13.440 51.632 13.536 ;
      RECT 0.048 14.208 51.632 14.304 ;
      RECT 0.048 14.976 51.632 15.072 ;
      RECT 0.048 15.744 51.632 15.840 ;
      RECT 0.048 16.512 51.632 16.608 ;
      RECT 0.048 17.280 51.632 17.376 ;
      RECT 0.048 18.048 51.632 18.144 ;
      RECT 0.048 18.816 51.632 18.912 ;
      RECT 0.048 19.584 51.632 19.680 ;
      RECT 0.048 20.352 51.632 20.448 ;
      RECT 0.048 21.120 51.632 21.216 ;
      RECT 0.048 21.888 51.632 21.984 ;
      RECT 0.048 22.656 51.632 22.752 ;
      RECT 0.048 23.424 51.632 23.520 ;
      RECT 0.048 24.192 51.632 24.288 ;
      RECT 0.048 24.960 51.632 25.056 ;
      RECT 0.048 25.728 51.632 25.824 ;
      RECT 0.048 26.496 51.632 26.592 ;
      RECT 0.048 27.264 51.632 27.360 ;
      RECT 0.048 28.032 51.632 28.128 ;
      RECT 0.048 28.800 51.632 28.896 ;
      RECT 0.048 29.568 51.632 29.664 ;
      RECT 0.048 30.336 51.632 30.432 ;
      RECT 0.048 31.104 51.632 31.200 ;
      RECT 0.048 31.872 51.632 31.968 ;
      RECT 0.048 32.640 51.632 32.736 ;
      RECT 0.048 33.408 51.632 33.504 ;
      RECT 0.048 34.176 51.632 34.272 ;
      RECT 0.048 34.944 51.632 35.040 ;
      RECT 0.048 35.712 51.632 35.808 ;
      RECT 0.048 36.480 51.632 36.576 ;
      RECT 0.048 37.248 51.632 37.344 ;
      RECT 0.048 38.016 51.632 38.112 ;
      RECT 0.048 38.784 51.632 38.880 ;
      RECT 0.048 39.552 51.632 39.648 ;
      RECT 0.048 40.320 51.632 40.416 ;
      RECT 0.048 41.088 51.632 41.184 ;
      RECT 0.048 41.856 51.632 41.952 ;
      RECT 0.048 42.624 51.632 42.720 ;
      RECT 0.048 43.392 51.632 43.488 ;
      RECT 0.048 44.160 51.632 44.256 ;
      RECT 0.048 44.928 51.632 45.024 ;
      RECT 0.048 45.696 51.632 45.792 ;
    END
  END VDD
  OBS
    LAYER M1 ;
    RECT 0 0 51.680 46.200 ;
    LAYER M2 ;
    RECT 0 0 51.680 46.200 ;
    LAYER M3 ;
    RECT 0 0 51.680 46.200 ;
    LAYER M4 ;
    RECT 0 0 51.680 46.200 ;
  END
END fakeram7_tdp_512x64

END LIBRARY
